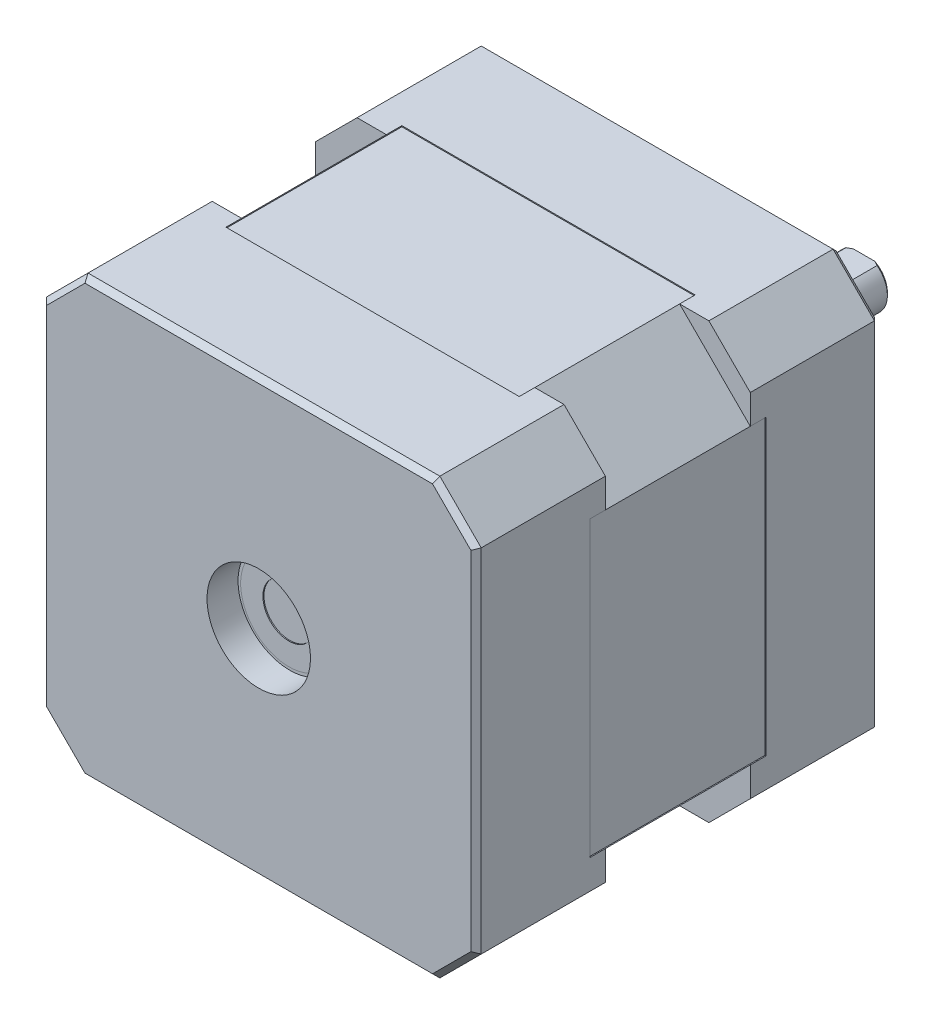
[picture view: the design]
ISO-10303-21;
HEADER;
FILE_DESCRIPTION(('STEP AP214'),'2;1');
FILE_NAME('part.step','',(''),(''),'','','');
FILE_SCHEMA(('AUTOMOTIVE_DESIGN { 1 0 10303 214 1 1 1 1 }'));
ENDSEC;
DATA;
#1=APPLICATION_CONTEXT('core data for automotive mechanical design processes');
#2=APPLICATION_PROTOCOL_DEFINITION('international standard','automotive_design',2000,#1);
#3=PRODUCT_CONTEXT('',#1,'mechanical');
#4=PRODUCT('Part','Part','',(#3));
#5=PRODUCT_RELATED_PRODUCT_CATEGORY('part','',(#4));
#6=PRODUCT_DEFINITION_FORMATION('','',#4);
#7=PRODUCT_DEFINITION_CONTEXT('part definition',#1,'design');
#8=PRODUCT_DEFINITION('design','',#6,#7);
#9=PRODUCT_DEFINITION_SHAPE('','',#8);
#10=(LENGTH_UNIT() NAMED_UNIT(*) SI_UNIT(.MILLI.,.METRE.));
#11=(NAMED_UNIT(*) PLANE_ANGLE_UNIT() SI_UNIT($,.RADIAN.));
#12=(NAMED_UNIT(*) SI_UNIT($,.STERADIAN.) SOLID_ANGLE_UNIT());
#13=UNCERTAINTY_MEASURE_WITH_UNIT(LENGTH_MEASURE(1.E-05),#10,'distance_accuracy_value','');
#14=(GEOMETRIC_REPRESENTATION_CONTEXT(3) GLOBAL_UNCERTAINTY_ASSIGNED_CONTEXT((#13)) GLOBAL_UNIT_ASSIGNED_CONTEXT((#10,
#11,#12)) REPRESENTATION_CONTEXT('',''));
#15=CARTESIAN_POINT('',(0.,0.,0.));
#16=DIRECTION('',(0.,0.,1.));
#17=DIRECTION('',(1.,0.,0.));
#18=AXIS2_PLACEMENT_3D('',#15,#16,#17);
#19=CARTESIAN_POINT('',(0.,0.,36.));
#20=DIRECTION('',(0.,0.,1.));
#21=DIRECTION('',(1.,0.,0.));
#22=AXIS2_PLACEMENT_3D('',#19,#20,#21);
#23=PLANE('',#22);
#24=CARTESIAN_POINT('',(0.,0.,36.));
#25=DIRECTION('',(0.,0.,1.));
#26=DIRECTION('',(1.,0.,0.));
#27=AXIS2_PLACEMENT_3D('',#24,#25,#26);
#28=CIRCLE('',#27,5.);
#29=CARTESIAN_POINT('',(5.,0.,36.));
#30=VERTEX_POINT('',#29);
#31=EDGE_CURVE('E1002',#30,#30,#28,.T.);
#32=ORIENTED_EDGE('',*,*,#31,.T.);
#33=EDGE_LOOP('',(#32));
#34=FACE_BOUND('',#33,.T.);
#35=CARTESIAN_POINT('',(0.,0.,36.));
#36=DIRECTION('',(0.,0.,1.));
#37=DIRECTION('',(1.,0.,0.));
#38=AXIS2_PLACEMENT_3D('',#35,#36,#37);
#39=CIRCLE('',#38,4.65);
#40=CARTESIAN_POINT('',(4.65,0.,36.));
#41=VERTEX_POINT('',#40);
#42=EDGE_CURVE('E995',#41,#41,#39,.T.);
#43=ORIENTED_EDGE('',*,*,#42,.F.);
#44=EDGE_LOOP('',(#43));
#45=FACE_BOUND('',#44,.T.);
#46=ADVANCED_FACE('F35',(#34,#45),#23,.T.);
#47=CARTESIAN_POINT('',(21.,21.,39.));
#48=DIRECTION('',(-1.,0.,0.));
#49=DIRECTION('',(0.,-1.,0.));
#50=AXIS2_PLACEMENT_3D('',#47,#48,#49);
#51=PLANE('',#50);
#52=DIRECTION('',(0.,1.,0.));
#53=VECTOR('',#52,1.);
#54=CARTESIAN_POINT('',(21.,21.,26.5));
#55=LINE('',#54,#53);
#56=CARTESIAN_POINT('',(21.,-17.,26.5));
#57=VERTEX_POINT('',#56);
#58=CARTESIAN_POINT('',(21.0000000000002,-14.1715728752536,26.5));
#59=VERTEX_POINT('',#58);
#60=EDGE_CURVE('E552',#57,#59,#55,.T.);
#61=ORIENTED_EDGE('',*,*,#60,.T.);
#62=DIRECTION('',(0.,0.,-1.));
#63=VECTOR('',#62,1.);
#64=CARTESIAN_POINT('',(21.0000000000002,-14.1715728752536,12.5));
#65=LINE('',#64,#63);
#66=CARTESIAN_POINT('',(21.0000000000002,-14.1715728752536,28.));
#67=VERTEX_POINT('',#66);
#68=EDGE_CURVE('E395',#67,#59,#65,.T.);
#69=ORIENTED_EDGE('',*,*,#68,.F.);
#70=DIRECTION('',(0.,-1.,0.));
#71=VECTOR('',#70,1.);
#72=CARTESIAN_POINT('',(20.9999999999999,14.1715728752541,28.));
#73=LINE('',#72,#71);
#74=CARTESIAN_POINT('',(20.9999999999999,14.1715728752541,28.));
#75=VERTEX_POINT('',#74);
#76=EDGE_CURVE('E392',#75,#67,#73,.T.);
#77=ORIENTED_EDGE('',*,*,#76,.F.);
#78=DIRECTION('',(0.,0.,1.));
#79=VECTOR('',#78,1.);
#80=CARTESIAN_POINT('',(20.9999999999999,14.1715728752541,26.5));
#81=LINE('',#80,#79);
#82=CARTESIAN_POINT('',(20.9999999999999,14.1715728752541,26.5));
#83=VERTEX_POINT('',#82);
#84=EDGE_CURVE('E376',#83,#75,#81,.T.);
#85=ORIENTED_EDGE('',*,*,#84,.F.);
#86=DIRECTION('',(0.,1.,0.));
#87=VECTOR('',#86,1.);
#88=CARTESIAN_POINT('',(21.,21.,26.5));
#89=LINE('',#88,#87);
#90=CARTESIAN_POINT('',(21.,17.,26.5));
#91=VERTEX_POINT('',#90);
#92=EDGE_CURVE('E532',#83,#91,#89,.T.);
#93=ORIENTED_EDGE('',*,*,#92,.T.);
#94=DIRECTION('',(0.,0.,1.));
#95=VECTOR('',#94,1.);
#96=CARTESIAN_POINT('',(21.,17.,39.));
#97=LINE('',#96,#95);
#98=CARTESIAN_POINT('',(21.,17.,38.5));
#99=VERTEX_POINT('',#98);
#100=EDGE_CURVE('E629',#91,#99,#97,.T.);
#101=ORIENTED_EDGE('',*,*,#100,.T.);
#102=DIRECTION('',(0.,-1.,0.));
#103=VECTOR('',#102,1.);
#104=CARTESIAN_POINT('',(21.,-17.,38.5));
#105=LINE('',#104,#103);
#106=CARTESIAN_POINT('',(21.,-17.,38.5));
#107=VERTEX_POINT('',#106);
#108=EDGE_CURVE('E710',#99,#107,#105,.T.);
#109=ORIENTED_EDGE('',*,*,#108,.T.);
#110=DIRECTION('',(0.,0.,-1.));
#111=VECTOR('',#110,1.);
#112=CARTESIAN_POINT('',(21.,-17.,39.));
#113=LINE('',#112,#111);
#114=EDGE_CURVE('E630',#107,#57,#113,.T.);
#115=ORIENTED_EDGE('',*,*,#114,.T.);
#116=EDGE_LOOP('',(#61,#69,#77,#85,#93,#101,#109,#115));
#117=FACE_BOUND('',#116,.T.);
#118=ADVANCED_FACE('F864',(#117),#51,.F.);
#119=CARTESIAN_POINT('',(-21.,-21.,39.));
#120=DIRECTION('',(0.,1.,0.));
#121=DIRECTION('',(0.,0.,1.));
#122=AXIS2_PLACEMENT_3D('',#119,#120,#121);
#123=PLANE('',#122);
#124=DIRECTION('',(1.,0.,0.));
#125=VECTOR('',#124,1.);
#126=CARTESIAN_POINT('',(-21.,-21.,26.5));
#127=LINE('',#126,#125);
#128=CARTESIAN_POINT('',(-17.,-21.,26.5));
#129=VERTEX_POINT('',#128);
#130=CARTESIAN_POINT('',(-14.1715728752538,-21.,26.5));
#131=VERTEX_POINT('',#130);
#132=EDGE_CURVE('E569',#129,#131,#127,.T.);
#133=ORIENTED_EDGE('',*,*,#132,.T.);
#134=DIRECTION('',(0.,0.,-1.));
#135=VECTOR('',#134,1.);
#136=CARTESIAN_POINT('',(-14.1715728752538,-21.,12.5));
#137=LINE('',#136,#135);
#138=CARTESIAN_POINT('',(-14.1715728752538,-21.,28.));
#139=VERTEX_POINT('',#138);
#140=EDGE_CURVE('E424',#139,#131,#137,.T.);
#141=ORIENTED_EDGE('',*,*,#140,.F.);
#142=DIRECTION('',(-1.,0.,0.));
#143=VECTOR('',#142,1.);
#144=CARTESIAN_POINT('',(14.1715728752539,-21.,28.));
#145=LINE('',#144,#143);
#146=CARTESIAN_POINT('',(14.1715728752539,-21.,28.));
#147=VERTEX_POINT('',#146);
#148=EDGE_CURVE('E420',#147,#139,#145,.T.);
#149=ORIENTED_EDGE('',*,*,#148,.F.);
#150=DIRECTION('',(0.,0.,1.));
#151=VECTOR('',#150,1.);
#152=CARTESIAN_POINT('',(14.1715728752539,-21.,26.5));
#153=LINE('',#152,#151);
#154=CARTESIAN_POINT('',(14.1715728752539,-21.,26.5));
#155=VERTEX_POINT('',#154);
#156=EDGE_CURVE('E401',#155,#147,#153,.T.);
#157=ORIENTED_EDGE('',*,*,#156,.F.);
#158=DIRECTION('',(1.,0.,0.));
#159=VECTOR('',#158,1.);
#160=CARTESIAN_POINT('',(-21.,-21.,26.5));
#161=LINE('',#160,#159);
#162=CARTESIAN_POINT('',(17.,-21.,26.5));
#163=VERTEX_POINT('',#162);
#164=EDGE_CURVE('E549',#155,#163,#161,.T.);
#165=ORIENTED_EDGE('',*,*,#164,.T.);
#166=DIRECTION('',(0.,0.,1.));
#167=VECTOR('',#166,1.);
#168=CARTESIAN_POINT('',(17.,-21.,39.));
#169=LINE('',#168,#167);
#170=CARTESIAN_POINT('',(17.,-21.,38.5));
#171=VERTEX_POINT('',#170);
#172=EDGE_CURVE('E637',#163,#171,#169,.T.);
#173=ORIENTED_EDGE('',*,*,#172,.T.);
#174=DIRECTION('',(-1.,0.,0.));
#175=VECTOR('',#174,1.);
#176=CARTESIAN_POINT('',(-17.,-21.,38.5));
#177=LINE('',#176,#175);
#178=CARTESIAN_POINT('',(-17.,-21.,38.5));
#179=VERTEX_POINT('',#178);
#180=EDGE_CURVE('E700',#171,#179,#177,.T.);
#181=ORIENTED_EDGE('',*,*,#180,.T.);
#182=DIRECTION('',(0.,0.,-1.));
#183=VECTOR('',#182,1.);
#184=CARTESIAN_POINT('',(-17.,-21.,39.));
#185=LINE('',#184,#183);
#186=EDGE_CURVE('E634',#179,#129,#185,.T.);
#187=ORIENTED_EDGE('',*,*,#186,.T.);
#188=EDGE_LOOP('',(#133,#141,#149,#157,#165,#173,#181,#187));
#189=FACE_BOUND('',#188,.T.);
#190=ADVANCED_FACE('F850',(#189),#123,.F.);
#191=CARTESIAN_POINT('',(-21.,21.,39.));
#192=DIRECTION('',(1.,0.,0.));
#193=DIRECTION('',(0.,1.,0.));
#194=AXIS2_PLACEMENT_3D('',#191,#192,#193);
#195=PLANE('',#194);
#196=DIRECTION('',(0.,-1.,0.));
#197=VECTOR('',#196,1.);
#198=CARTESIAN_POINT('',(-21.,21.,26.5));
#199=LINE('',#198,#197);
#200=CARTESIAN_POINT('',(-21.,17.,26.5));
#201=VERTEX_POINT('',#200);
#202=CARTESIAN_POINT('',(-21.,14.1715728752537,26.5));
#203=VERTEX_POINT('',#202);
#204=EDGE_CURVE('E511',#201,#203,#199,.T.);
#205=ORIENTED_EDGE('',*,*,#204,.T.);
#206=DIRECTION('',(0.,0.,-1.));
#207=VECTOR('',#206,1.);
#208=CARTESIAN_POINT('',(-21.0000000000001,14.1715728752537,12.5));
#209=LINE('',#208,#207);
#210=CARTESIAN_POINT('',(-21.0000000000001,14.1715728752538,28.));
#211=VERTEX_POINT('',#210);
#212=EDGE_CURVE('E456',#211,#203,#209,.T.);
#213=ORIENTED_EDGE('',*,*,#212,.F.);
#214=DIRECTION('',(0.,1.,0.));
#215=VECTOR('',#214,1.);
#216=CARTESIAN_POINT('',(-21.,-14.1715728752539,28.));
#217=LINE('',#216,#215);
#218=CARTESIAN_POINT('',(-21.,-14.1715728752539,28.));
#219=VERTEX_POINT('',#218);
#220=EDGE_CURVE('E452',#219,#211,#217,.T.);
#221=ORIENTED_EDGE('',*,*,#220,.F.);
#222=DIRECTION('',(0.,0.,1.));
#223=VECTOR('',#222,1.);
#224=CARTESIAN_POINT('',(-21.,-14.1715728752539,26.5));
#225=LINE('',#224,#223);
#226=CARTESIAN_POINT('',(-21.,-14.1715728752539,26.5));
#227=VERTEX_POINT('',#226);
#228=EDGE_CURVE('E430',#227,#219,#225,.T.);
#229=ORIENTED_EDGE('',*,*,#228,.F.);
#230=DIRECTION('',(0.,-1.,0.));
#231=VECTOR('',#230,1.);
#232=CARTESIAN_POINT('',(-21.,21.,26.5));
#233=LINE('',#232,#231);
#234=CARTESIAN_POINT('',(-21.,-17.,26.5));
#235=VERTEX_POINT('',#234);
#236=EDGE_CURVE('E572',#227,#235,#233,.T.);
#237=ORIENTED_EDGE('',*,*,#236,.T.);
#238=DIRECTION('',(0.,0.,1.));
#239=VECTOR('',#238,1.);
#240=CARTESIAN_POINT('',(-21.,-17.,39.));
#241=LINE('',#240,#239);
#242=CARTESIAN_POINT('',(-21.,-17.,38.5));
#243=VERTEX_POINT('',#242);
#244=EDGE_CURVE('E649',#235,#243,#241,.T.);
#245=ORIENTED_EDGE('',*,*,#244,.T.);
#246=DIRECTION('',(0.,1.,0.));
#247=VECTOR('',#246,1.);
#248=CARTESIAN_POINT('',(-21.,17.,38.5));
#249=LINE('',#248,#247);
#250=CARTESIAN_POINT('',(-21.,17.,38.5));
#251=VERTEX_POINT('',#250);
#252=EDGE_CURVE('E690',#243,#251,#249,.T.);
#253=ORIENTED_EDGE('',*,*,#252,.T.);
#254=DIRECTION('',(0.,0.,-1.));
#255=VECTOR('',#254,1.);
#256=CARTESIAN_POINT('',(-21.,17.,39.));
#257=LINE('',#256,#255);
#258=EDGE_CURVE('E654',#251,#201,#257,.T.);
#259=ORIENTED_EDGE('',*,*,#258,.T.);
#260=EDGE_LOOP('',(#205,#213,#221,#229,#237,#245,#253,#259));
#261=FACE_BOUND('',#260,.T.);
#262=ADVANCED_FACE('F855',(#261),#195,.F.);
#263=CARTESIAN_POINT('',(-21.,21.,39.));
#264=DIRECTION('',(0.,-1.,0.));
#265=DIRECTION('',(0.,0.,-1.));
#266=AXIS2_PLACEMENT_3D('',#263,#264,#265);
#267=PLANE('',#266);
#268=DIRECTION('',(-1.,0.,0.));
#269=VECTOR('',#268,1.);
#270=CARTESIAN_POINT('',(-21.,21.,26.5));
#271=LINE('',#270,#269);
#272=CARTESIAN_POINT('',(17.,21.,26.5));
#273=VERTEX_POINT('',#272);
#274=CARTESIAN_POINT('',(14.1715728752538,21.,26.5));
#275=VERTEX_POINT('',#274);
#276=EDGE_CURVE('E529',#273,#275,#271,.T.);
#277=ORIENTED_EDGE('',*,*,#276,.T.);
#278=DIRECTION('',(0.,0.,-1.));
#279=VECTOR('',#278,1.);
#280=CARTESIAN_POINT('',(14.1715728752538,21.,12.5));
#281=LINE('',#280,#279);
#282=CARTESIAN_POINT('',(14.1715728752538,21.,28.));
#283=VERTEX_POINT('',#282);
#284=EDGE_CURVE('E488',#283,#275,#281,.T.);
#285=ORIENTED_EDGE('',*,*,#284,.F.);
#286=DIRECTION('',(1.,0.,0.));
#287=VECTOR('',#286,1.);
#288=CARTESIAN_POINT('',(-14.1715728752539,21.,28.));
#289=LINE('',#288,#287);
#290=CARTESIAN_POINT('',(-14.1715728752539,21.,28.));
#291=VERTEX_POINT('',#290);
#292=EDGE_CURVE('E484',#291,#283,#289,.T.);
#293=ORIENTED_EDGE('',*,*,#292,.F.);
#294=DIRECTION('',(0.,0.,1.));
#295=VECTOR('',#294,1.);
#296=CARTESIAN_POINT('',(-14.1715728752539,21.,26.5));
#297=LINE('',#296,#295);
#298=CARTESIAN_POINT('',(-14.1715728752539,21.,26.5));
#299=VERTEX_POINT('',#298);
#300=EDGE_CURVE('E462',#299,#291,#297,.T.);
#301=ORIENTED_EDGE('',*,*,#300,.F.);
#302=DIRECTION('',(-1.,0.,0.));
#303=VECTOR('',#302,1.);
#304=CARTESIAN_POINT('',(-21.,21.,26.5));
#305=LINE('',#304,#303);
#306=CARTESIAN_POINT('',(-17.,21.,26.5));
#307=VERTEX_POINT('',#306);
#308=EDGE_CURVE('E514',#299,#307,#305,.T.);
#309=ORIENTED_EDGE('',*,*,#308,.T.);
#310=DIRECTION('',(0.,0.,1.));
#311=VECTOR('',#310,1.);
#312=CARTESIAN_POINT('',(-17.,21.,39.));
#313=LINE('',#312,#311);
#314=CARTESIAN_POINT('',(-17.,21.,38.5));
#315=VERTEX_POINT('',#314);
#316=EDGE_CURVE('E641',#307,#315,#313,.T.);
#317=ORIENTED_EDGE('',*,*,#316,.T.);
#318=DIRECTION('',(1.,0.,0.));
#319=VECTOR('',#318,1.);
#320=CARTESIAN_POINT('',(17.,21.,38.5));
#321=LINE('',#320,#319);
#322=CARTESIAN_POINT('',(17.,21.,38.5));
#323=VERTEX_POINT('',#322);
#324=EDGE_CURVE('E680',#315,#323,#321,.T.);
#325=ORIENTED_EDGE('',*,*,#324,.T.);
#326=DIRECTION('',(0.,0.,-1.));
#327=VECTOR('',#326,1.);
#328=CARTESIAN_POINT('',(17.,21.,39.));
#329=LINE('',#328,#327);
#330=EDGE_CURVE('E646',#323,#273,#329,.T.);
#331=ORIENTED_EDGE('',*,*,#330,.T.);
#332=EDGE_LOOP('',(#277,#285,#293,#301,#309,#317,#325,#331));
#333=FACE_BOUND('',#332,.T.);
#334=ADVANCED_FACE('F860',(#333),#267,.F.);
#335=CARTESIAN_POINT('',(-21.,17.,39.));
#336=DIRECTION('',(0.707106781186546,-0.707106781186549,0.));
#337=DIRECTION('',(0.,0.,-1.));
#338=AXIS2_PLACEMENT_3D('',#335,#336,#337);
#339=PLANE('',#338);
#340=DIRECTION('',(-0.707106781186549,-0.707106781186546,0.));
#341=VECTOR('',#340,1.);
#342=CARTESIAN_POINT('',(-21.,17.,26.5));
#343=LINE('',#342,#341);
#344=EDGE_CURVE('E1035',#201,#307,#343,.F.);
#345=ORIENTED_EDGE('',*,*,#344,.F.);
#346=ORIENTED_EDGE('',*,*,#258,.F.);
#347=DIRECTION('',(-0.707106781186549,-0.707106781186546,0.));
#348=VECTOR('',#347,1.);
#349=CARTESIAN_POINT('',(-21.,17.,38.5));
#350=LINE('',#349,#348);
#351=EDGE_CURVE('E684',#251,#315,#350,.F.);
#352=ORIENTED_EDGE('',*,*,#351,.T.);
#353=ORIENTED_EDGE('',*,*,#316,.F.);
#354=EDGE_LOOP('',(#345,#346,#352,#353));
#355=FACE_BOUND('',#354,.T.);
#356=ADVANCED_FACE('F879',(#355),#339,.F.);
#357=CARTESIAN_POINT('',(17.,21.,39.));
#358=DIRECTION('',(-0.707106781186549,-0.707106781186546,0.));
#359=DIRECTION('',(0.,0.,-1.));
#360=AXIS2_PLACEMENT_3D('',#357,#358,#359);
#361=PLANE('',#360);
#362=DIRECTION('',(-0.707106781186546,0.707106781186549,0.));
#363=VECTOR('',#362,1.);
#364=CARTESIAN_POINT('',(17.,21.,26.5));
#365=LINE('',#364,#363);
#366=EDGE_CURVE('E1060',#273,#91,#365,.F.);
#367=ORIENTED_EDGE('',*,*,#366,.F.);
#368=ORIENTED_EDGE('',*,*,#330,.F.);
#369=DIRECTION('',(-0.707106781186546,0.707106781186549,0.));
#370=VECTOR('',#369,1.);
#371=CARTESIAN_POINT('',(17.,21.,38.5));
#372=LINE('',#371,#370);
#373=EDGE_CURVE('E674',#323,#99,#372,.F.);
#374=ORIENTED_EDGE('',*,*,#373,.T.);
#375=ORIENTED_EDGE('',*,*,#100,.F.);
#376=EDGE_LOOP('',(#367,#368,#374,#375));
#377=FACE_BOUND('',#376,.T.);
#378=ADVANCED_FACE('F874',(#377),#361,.F.);
#379=CARTESIAN_POINT('',(21.,-17.,39.));
#380=DIRECTION('',(-0.707106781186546,0.707106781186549,0.));
#381=DIRECTION('',(0.,0.,-1.));
#382=AXIS2_PLACEMENT_3D('',#379,#380,#381);
#383=PLANE('',#382);
#384=DIRECTION('',(0.707106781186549,0.707106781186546,0.));
#385=VECTOR('',#384,1.);
#386=CARTESIAN_POINT('',(21.,-17.,26.5));
#387=LINE('',#386,#385);
#388=EDGE_CURVE('E1053',#57,#163,#387,.F.);
#389=ORIENTED_EDGE('',*,*,#388,.F.);
#390=ORIENTED_EDGE('',*,*,#114,.F.);
#391=DIRECTION('',(0.707106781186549,0.707106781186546,0.));
#392=VECTOR('',#391,1.);
#393=CARTESIAN_POINT('',(21.,-17.,38.5));
#394=LINE('',#393,#392);
#395=EDGE_CURVE('E704',#107,#171,#394,.F.);
#396=ORIENTED_EDGE('',*,*,#395,.T.);
#397=ORIENTED_EDGE('',*,*,#172,.F.);
#398=EDGE_LOOP('',(#389,#390,#396,#397));
#399=FACE_BOUND('',#398,.T.);
#400=ADVANCED_FACE('F869',(#399),#383,.F.);
#401=CARTESIAN_POINT('',(-17.,-21.,39.));
#402=DIRECTION('',(0.707106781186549,0.707106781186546,0.));
#403=DIRECTION('',(0.,0.,-1.));
#404=AXIS2_PLACEMENT_3D('',#401,#402,#403);
#405=PLANE('',#404);
#406=DIRECTION('',(0.707106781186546,-0.707106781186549,0.));
#407=VECTOR('',#406,1.);
#408=CARTESIAN_POINT('',(-17.,-21.,26.5));
#409=LINE('',#408,#407);
#410=EDGE_CURVE('E1044',#129,#235,#409,.F.);
#411=ORIENTED_EDGE('',*,*,#410,.F.);
#412=ORIENTED_EDGE('',*,*,#186,.F.);
#413=DIRECTION('',(0.707106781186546,-0.707106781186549,0.));
#414=VECTOR('',#413,1.);
#415=CARTESIAN_POINT('',(-17.,-21.,38.5));
#416=LINE('',#415,#414);
#417=EDGE_CURVE('E694',#179,#243,#416,.F.);
#418=ORIENTED_EDGE('',*,*,#417,.T.);
#419=ORIENTED_EDGE('',*,*,#244,.F.);
#420=EDGE_LOOP('',(#411,#412,#418,#419));
#421=FACE_BOUND('',#420,.T.);
#422=ADVANCED_FACE('F834',(#421),#405,.F.);
#423=CARTESIAN_POINT('',(0.,0.,0.5));
#424=DIRECTION('',(0.,0.,-1.));
#425=DIRECTION('',(-1.,0.,0.));
#426=AXIS2_PLACEMENT_3D('',#423,#424,#425);
#427=PLANE('',#426);
#428=CARTESIAN_POINT('',(0.,0.,0.5));
#429=DIRECTION('',(0.,0.,-1.));
#430=DIRECTION('',(-1.,0.,0.));
#431=AXIS2_PLACEMENT_3D('',#428,#429,#430);
#432=CIRCLE('',#431,4.75);
#433=CARTESIAN_POINT('',(-4.75,0.,0.5));
#434=VERTEX_POINT('',#433);
#435=EDGE_CURVE('E782',#434,#434,#432,.F.);
#436=ORIENTED_EDGE('',*,*,#435,.F.);
#437=EDGE_LOOP('',(#436));
#438=FACE_BOUND('',#437,.T.);
#439=CARTESIAN_POINT('',(0.,0.,0.5));
#440=DIRECTION('',(0.,0.,-1.));
#441=DIRECTION('',(-1.,0.,0.));
#442=AXIS2_PLACEMENT_3D('',#439,#440,#441);
#443=CIRCLE('',#442,2.5);
#444=CARTESIAN_POINT('',(-2.5,0.,0.5));
#445=VERTEX_POINT('',#444);
#446=EDGE_CURVE('E612',#445,#445,#443,.T.);
#447=ORIENTED_EDGE('',*,*,#446,.F.);
#448=EDGE_LOOP('',(#447));
#449=FACE_BOUND('',#448,.T.);
#450=ADVANCED_FACE('F830',(#438,#449),#427,.T.);
#451=CARTESIAN_POINT('',(0.,0.,0.5));
#452=DIRECTION('',(0.,0.,-1.));
#453=DIRECTION('',(-1.,0.,0.));
#454=AXIS2_PLACEMENT_3D('',#451,#452,#453);
#455=CIRCLE('',#454,14.);
#456=CARTESIAN_POINT('',(-14.,0.,0.5));
#457=VERTEX_POINT('',#456);
#458=EDGE_CURVE('E731',#457,#457,#455,.T.);
#459=ORIENTED_EDGE('',*,*,#458,.T.);
#460=EDGE_LOOP('',(#459));
#461=FACE_BOUND('',#460,.T.);
#462=CARTESIAN_POINT('',(0.,0.,0.5));
#463=DIRECTION('',(0.,0.,-1.));
#464=DIRECTION('',(-1.,0.,0.));
#465=AXIS2_PLACEMENT_3D('',#462,#463,#464);
#466=CIRCLE('',#465,11.);
#467=CARTESIAN_POINT('',(-11.,0.,0.5));
#468=VERTEX_POINT('',#467);
#469=EDGE_CURVE('E618',#468,#468,#466,.T.);
#470=ORIENTED_EDGE('',*,*,#469,.F.);
#471=EDGE_LOOP('',(#470));
#472=FACE_BOUND('',#471,.T.);
#473=ADVANCED_FACE('F833',(#461,#472),#427,.T.);
#474=DIRECTION('',(0.,1.,0.));
#475=VECTOR('',#474,1.);
#476=CARTESIAN_POINT('',(20.9999999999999,14.1715728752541,11.));
#477=LINE('',#476,#475);
#478=CARTESIAN_POINT('',(21.0000000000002,-14.1715728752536,11.));
#479=VERTEX_POINT('',#478);
#480=CARTESIAN_POINT('',(20.9999999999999,14.1715728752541,11.));
#481=VERTEX_POINT('',#480);
#482=EDGE_CURVE('E370',#479,#481,#477,.T.);
#483=ORIENTED_EDGE('',*,*,#482,.F.);
#484=CARTESIAN_POINT('',(21.0000000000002,-14.1715728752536,12.5));
#485=VERTEX_POINT('',#484);
#486=EDGE_CURVE('E394',#485,#479,#65,.T.);
#487=ORIENTED_EDGE('',*,*,#486,.F.);
#488=DIRECTION('',(0.,-1.,0.));
#489=VECTOR('',#488,1.);
#490=CARTESIAN_POINT('',(21.,21.,12.5));
#491=LINE('',#490,#489);
#492=CARTESIAN_POINT('',(21.,-17.,12.5));
#493=VERTEX_POINT('',#492);
#494=EDGE_CURVE('E546',#485,#493,#491,.T.);
#495=ORIENTED_EDGE('',*,*,#494,.T.);
#496=CARTESIAN_POINT('',(21.,-17.,0.5));
#497=VERTEX_POINT('',#496);
#498=EDGE_CURVE('E628',#493,#497,#113,.T.);
#499=ORIENTED_EDGE('',*,*,#498,.T.);
#500=DIRECTION('',(0.,1.,0.));
#501=VECTOR('',#500,1.);
#502=CARTESIAN_POINT('',(21.,21.,0.5));
#503=LINE('',#502,#501);
#504=CARTESIAN_POINT('',(21.,17.,0.5));
#505=VERTEX_POINT('',#504);
#506=EDGE_CURVE('E712',#497,#505,#503,.T.);
#507=ORIENTED_EDGE('',*,*,#506,.T.);
#508=CARTESIAN_POINT('',(21.,17.,12.5));
#509=VERTEX_POINT('',#508);
#510=EDGE_CURVE('E625',#505,#509,#97,.T.);
#511=ORIENTED_EDGE('',*,*,#510,.T.);
#512=DIRECTION('',(0.,-1.,0.));
#513=VECTOR('',#512,1.);
#514=CARTESIAN_POINT('',(21.,21.,12.5));
#515=LINE('',#514,#513);
#516=CARTESIAN_POINT('',(21.,14.1715728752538,12.5));
#517=VERTEX_POINT('',#516);
#518=EDGE_CURVE('E59',#509,#517,#515,.T.);
#519=ORIENTED_EDGE('',*,*,#518,.T.);
#520=EDGE_CURVE('E390',#481,#517,#81,.T.);
#521=ORIENTED_EDGE('',*,*,#520,.F.);
#522=EDGE_LOOP('',(#483,#487,#495,#499,#507,#511,#519,#521));
#523=FACE_BOUND('',#522,.T.);
#524=ADVANCED_FACE('F858',(#523),#51,.F.);
#525=DIRECTION('',(-1.,0.,0.));
#526=VECTOR('',#525,1.);
#527=CARTESIAN_POINT('',(-14.1715728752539,21.,11.));
#528=LINE('',#527,#526);
#529=CARTESIAN_POINT('',(14.1715728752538,21.,11.));
#530=VERTEX_POINT('',#529);
#531=CARTESIAN_POINT('',(-14.1715728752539,21.,11.));
#532=VERTEX_POINT('',#531);
#533=EDGE_CURVE('E473',#530,#532,#528,.T.);
#534=ORIENTED_EDGE('',*,*,#533,.F.);
#535=CARTESIAN_POINT('',(14.1715728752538,21.,12.5));
#536=VERTEX_POINT('',#535);
#537=EDGE_CURVE('E487',#536,#530,#281,.T.);
#538=ORIENTED_EDGE('',*,*,#537,.F.);
#539=DIRECTION('',(1.,0.,0.));
#540=VECTOR('',#539,1.);
#541=CARTESIAN_POINT('',(-21.,21.,12.5));
#542=LINE('',#541,#540);
#543=CARTESIAN_POINT('',(17.,21.,12.5));
#544=VERTEX_POINT('',#543);
#545=EDGE_CURVE('E525',#536,#544,#542,.T.);
#546=ORIENTED_EDGE('',*,*,#545,.T.);
#547=CARTESIAN_POINT('',(17.,21.,0.5));
#548=VERTEX_POINT('',#547);
#549=EDGE_CURVE('E645',#544,#548,#329,.T.);
#550=ORIENTED_EDGE('',*,*,#549,.T.);
#551=DIRECTION('',(-1.,0.,0.));
#552=VECTOR('',#551,1.);
#553=CARTESIAN_POINT('',(-21.,21.,0.5));
#554=LINE('',#553,#552);
#555=CARTESIAN_POINT('',(-17.,21.,0.5));
#556=VERTEX_POINT('',#555);
#557=EDGE_CURVE('E682',#548,#556,#554,.T.);
#558=ORIENTED_EDGE('',*,*,#557,.T.);
#559=CARTESIAN_POINT('',(-17.,21.,12.5));
#560=VERTEX_POINT('',#559);
#561=EDGE_CURVE('E642',#556,#560,#313,.T.);
#562=ORIENTED_EDGE('',*,*,#561,.T.);
#563=DIRECTION('',(1.,0.,0.));
#564=VECTOR('',#563,1.);
#565=CARTESIAN_POINT('',(-21.,21.,12.5));
#566=LINE('',#565,#564);
#567=CARTESIAN_POINT('',(-14.1715728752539,21.,12.5));
#568=VERTEX_POINT('',#567);
#569=EDGE_CURVE('E51',#560,#568,#566,.T.);
#570=ORIENTED_EDGE('',*,*,#569,.T.);
#571=EDGE_CURVE('E482',#532,#568,#297,.T.);
#572=ORIENTED_EDGE('',*,*,#571,.F.);
#573=EDGE_LOOP('',(#534,#538,#546,#550,#558,#562,#570,#572));
#574=FACE_BOUND('',#573,.T.);
#575=ADVANCED_FACE('F853',(#574),#267,.F.);
#576=DIRECTION('',(0.,-1.,0.));
#577=VECTOR('',#576,1.);
#578=CARTESIAN_POINT('',(-21.,-14.1715728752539,11.));
#579=LINE('',#578,#577);
#580=CARTESIAN_POINT('',(-21.0000000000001,14.1715728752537,11.));
#581=VERTEX_POINT('',#580);
#582=CARTESIAN_POINT('',(-21.,-14.1715728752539,11.));
#583=VERTEX_POINT('',#582);
#584=EDGE_CURVE('E441',#581,#583,#579,.T.);
#585=ORIENTED_EDGE('',*,*,#584,.F.);
#586=CARTESIAN_POINT('',(-21.0000000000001,14.1715728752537,12.5));
#587=VERTEX_POINT('',#586);
#588=EDGE_CURVE('E455',#587,#581,#209,.T.);
#589=ORIENTED_EDGE('',*,*,#588,.F.);
#590=DIRECTION('',(0.,1.,0.));
#591=VECTOR('',#590,1.);
#592=CARTESIAN_POINT('',(-21.,21.,12.5));
#593=LINE('',#592,#591);
#594=CARTESIAN_POINT('',(-21.,17.,12.5));
#595=VERTEX_POINT('',#594);
#596=EDGE_CURVE('E507',#587,#595,#593,.T.);
#597=ORIENTED_EDGE('',*,*,#596,.T.);
#598=CARTESIAN_POINT('',(-21.,17.,0.5));
#599=VERTEX_POINT('',#598);
#600=EDGE_CURVE('E653',#595,#599,#257,.T.);
#601=ORIENTED_EDGE('',*,*,#600,.T.);
#602=DIRECTION('',(0.,-1.,0.));
#603=VECTOR('',#602,1.);
#604=CARTESIAN_POINT('',(-21.,21.,0.5));
#605=LINE('',#604,#603);
#606=CARTESIAN_POINT('',(-21.,-17.,0.5));
#607=VERTEX_POINT('',#606);
#608=EDGE_CURVE('E692',#599,#607,#605,.T.);
#609=ORIENTED_EDGE('',*,*,#608,.T.);
#610=CARTESIAN_POINT('',(-21.,-17.,12.5));
#611=VERTEX_POINT('',#610);
#612=EDGE_CURVE('E650',#607,#611,#241,.T.);
#613=ORIENTED_EDGE('',*,*,#612,.T.);
#614=DIRECTION('',(0.,1.,0.));
#615=VECTOR('',#614,1.);
#616=CARTESIAN_POINT('',(-21.,21.,12.5));
#617=LINE('',#616,#615);
#618=CARTESIAN_POINT('',(-21.,-14.1715728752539,12.5));
#619=VERTEX_POINT('',#618);
#620=EDGE_CURVE('E566',#611,#619,#617,.T.);
#621=ORIENTED_EDGE('',*,*,#620,.T.);
#622=EDGE_CURVE('E450',#583,#619,#225,.T.);
#623=ORIENTED_EDGE('',*,*,#622,.F.);
#624=EDGE_LOOP('',(#585,#589,#597,#601,#609,#613,#621,#623));
#625=FACE_BOUND('',#624,.T.);
#626=ADVANCED_FACE('F848',(#625),#195,.F.);
#627=DIRECTION('',(1.,0.,0.));
#628=VECTOR('',#627,1.);
#629=CARTESIAN_POINT('',(14.1715728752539,-21.,11.));
#630=LINE('',#629,#628);
#631=CARTESIAN_POINT('',(-14.1715728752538,-21.,11.));
#632=VERTEX_POINT('',#631);
#633=CARTESIAN_POINT('',(14.1715728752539,-21.,11.));
#634=VERTEX_POINT('',#633);
#635=EDGE_CURVE('E409',#632,#634,#630,.T.);
#636=ORIENTED_EDGE('',*,*,#635,.F.);
#637=CARTESIAN_POINT('',(-14.1715728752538,-21.,12.5));
#638=VERTEX_POINT('',#637);
#639=EDGE_CURVE('E423',#638,#632,#137,.T.);
#640=ORIENTED_EDGE('',*,*,#639,.F.);
#641=DIRECTION('',(-1.,0.,0.));
#642=VECTOR('',#641,1.);
#643=CARTESIAN_POINT('',(-21.,-21.,12.5));
#644=LINE('',#643,#642);
#645=CARTESIAN_POINT('',(-17.,-21.,12.5));
#646=VERTEX_POINT('',#645);
#647=EDGE_CURVE('E563',#638,#646,#644,.T.);
#648=ORIENTED_EDGE('',*,*,#647,.T.);
#649=CARTESIAN_POINT('',(-17.,-21.,0.5));
#650=VERTEX_POINT('',#649);
#651=EDGE_CURVE('E633',#646,#650,#185,.T.);
#652=ORIENTED_EDGE('',*,*,#651,.T.);
#653=DIRECTION('',(1.,0.,0.));
#654=VECTOR('',#653,1.);
#655=CARTESIAN_POINT('',(-21.,-21.,0.5));
#656=LINE('',#655,#654);
#657=CARTESIAN_POINT('',(17.,-21.,0.5));
#658=VERTEX_POINT('',#657);
#659=EDGE_CURVE('E702',#650,#658,#656,.T.);
#660=ORIENTED_EDGE('',*,*,#659,.T.);
#661=CARTESIAN_POINT('',(17.,-21.,12.5));
#662=VERTEX_POINT('',#661);
#663=EDGE_CURVE('E638',#658,#662,#169,.T.);
#664=ORIENTED_EDGE('',*,*,#663,.T.);
#665=DIRECTION('',(-1.,0.,0.));
#666=VECTOR('',#665,1.);
#667=CARTESIAN_POINT('',(-21.,-21.,12.5));
#668=LINE('',#667,#666);
#669=CARTESIAN_POINT('',(14.1715728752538,-21.,12.5));
#670=VERTEX_POINT('',#669);
#671=EDGE_CURVE('E543',#662,#670,#668,.T.);
#672=ORIENTED_EDGE('',*,*,#671,.T.);
#673=EDGE_CURVE('E418',#634,#670,#153,.T.);
#674=ORIENTED_EDGE('',*,*,#673,.F.);
#675=EDGE_LOOP('',(#636,#640,#648,#652,#660,#664,#672,#674));
#676=FACE_BOUND('',#675,.T.);
#677=ADVANCED_FACE('F840',(#676),#123,.F.);
#678=CARTESIAN_POINT('',(0.,0.,39.));
#679=DIRECTION('',(0.,0.,1.));
#680=DIRECTION('',(1.,0.,0.));
#681=AXIS2_PLACEMENT_3D('',#678,#679,#680);
#682=PLANE('',#681);
#683=CARTESIAN_POINT('',(0.,0.,39.));
#684=DIRECTION('',(0.,0.,1.));
#685=DIRECTION('',(1.,0.,0.));
#686=AXIS2_PLACEMENT_3D('',#683,#684,#685);
#687=CIRCLE('',#686,5.);
#688=CARTESIAN_POINT('',(5.,0.,39.));
#689=VERTEX_POINT('',#688);
#690=EDGE_CURVE('E1000',#689,#689,#687,.T.);
#691=ORIENTED_EDGE('',*,*,#690,.F.);
#692=EDGE_LOOP('',(#691));
#693=FACE_BOUND('',#692,.T.);
#694=DIRECTION('',(0.,-1.,0.));
#695=VECTOR('',#694,1.);
#696=CARTESIAN_POINT('',(-20.5,-17.,39.));
#697=LINE('',#696,#695);
#698=CARTESIAN_POINT('',(-20.5,16.7928932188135,39.));
#699=VERTEX_POINT('',#698);
#700=CARTESIAN_POINT('',(-20.5,-16.7928932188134,39.));
#701=VERTEX_POINT('',#700);
#702=EDGE_CURVE('E726',#699,#701,#697,.T.);
#703=ORIENTED_EDGE('',*,*,#702,.T.);
#704=DIRECTION('',(0.707106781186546,-0.707106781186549,0.));
#705=VECTOR('',#704,1.);
#706=CARTESIAN_POINT('',(-18.6464466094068,-18.6464466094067,39.));
#707=LINE('',#706,#705);
#708=CARTESIAN_POINT('',(-16.7928932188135,-20.5,39.));
#709=VERTEX_POINT('',#708);
#710=EDGE_CURVE('E728',#701,#709,#707,.T.);
#711=ORIENTED_EDGE('',*,*,#710,.T.);
#712=DIRECTION('',(1.,0.,0.));
#713=VECTOR('',#712,1.);
#714=CARTESIAN_POINT('',(17.,-20.5,39.));
#715=LINE('',#714,#713);
#716=CARTESIAN_POINT('',(16.7928932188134,-20.5,39.));
#717=VERTEX_POINT('',#716);
#718=EDGE_CURVE('E714',#709,#717,#715,.T.);
#719=ORIENTED_EDGE('',*,*,#718,.T.);
#720=DIRECTION('',(0.707106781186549,0.707106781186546,0.));
#721=VECTOR('',#720,1.);
#722=CARTESIAN_POINT('',(18.6464466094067,-18.6464466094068,39.));
#723=LINE('',#722,#721);
#724=CARTESIAN_POINT('',(20.5,-16.7928932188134,39.));
#725=VERTEX_POINT('',#724);
#726=EDGE_CURVE('E716',#717,#725,#723,.T.);
#727=ORIENTED_EDGE('',*,*,#726,.T.);
#728=DIRECTION('',(0.,1.,0.));
#729=VECTOR('',#728,1.);
#730=CARTESIAN_POINT('',(20.5,17.,39.));
#731=LINE('',#730,#729);
#732=CARTESIAN_POINT('',(20.5,16.7928932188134,39.));
#733=VERTEX_POINT('',#732);
#734=EDGE_CURVE('E718',#725,#733,#731,.T.);
#735=ORIENTED_EDGE('',*,*,#734,.T.);
#736=DIRECTION('',(-0.707106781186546,0.707106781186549,0.));
#737=VECTOR('',#736,1.);
#738=CARTESIAN_POINT('',(18.6464466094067,18.6464466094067,39.));
#739=LINE('',#738,#737);
#740=CARTESIAN_POINT('',(16.7928932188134,20.5,39.));
#741=VERTEX_POINT('',#740);
#742=EDGE_CURVE('E720',#733,#741,#739,.T.);
#743=ORIENTED_EDGE('',*,*,#742,.T.);
#744=DIRECTION('',(-1.,0.,0.));
#745=VECTOR('',#744,1.);
#746=CARTESIAN_POINT('',(-17.,20.5,39.));
#747=LINE('',#746,#745);
#748=CARTESIAN_POINT('',(-16.7928932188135,20.5,39.));
#749=VERTEX_POINT('',#748);
#750=EDGE_CURVE('E722',#741,#749,#747,.T.);
#751=ORIENTED_EDGE('',*,*,#750,.T.);
#752=DIRECTION('',(-0.707106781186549,-0.707106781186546,0.));
#753=VECTOR('',#752,1.);
#754=CARTESIAN_POINT('',(-18.6464466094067,18.6464466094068,39.));
#755=LINE('',#754,#753);
#756=EDGE_CURVE('E724',#749,#699,#755,.T.);
#757=ORIENTED_EDGE('',*,*,#756,.T.);
#758=EDGE_LOOP('',(#703,#711,#719,#727,#735,#743,#751,#757));
#759=FACE_BOUND('',#758,.T.);
#760=ADVANCED_FACE('F836',(#693,#759),#682,.T.);
#761=CARTESIAN_POINT('',(0.,0.,0.));
#762=DIRECTION('',(0.,0.,1.));
#763=DIRECTION('',(1.,0.,0.));
#764=AXIS2_PLACEMENT_3D('',#761,#762,#763);
#765=PLANE('',#764);
#766=CARTESIAN_POINT('',(15.3500000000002,-15.3499999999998,0.));
#767=DIRECTION('',(0.,0.,-1.));
#768=DIRECTION('',(0.,1.,0.));
#769=AXIS2_PLACEMENT_3D('',#766,#767,#768);
#770=CIRCLE('',#769,1.5);
#771=CARTESIAN_POINT('',(15.3500000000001,-13.8499999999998,0.));
#772=VERTEX_POINT('',#771);
#773=EDGE_CURVE('E577',#772,#772,#770,.T.);
#774=ORIENTED_EDGE('',*,*,#773,.F.);
#775=EDGE_LOOP('',(#774));
#776=FACE_BOUND('',#775,.T.);
#777=CARTESIAN_POINT('',(-15.35,-15.35,0.));
#778=DIRECTION('',(0.,0.,-1.));
#779=DIRECTION('',(1.,0.,0.));
#780=AXIS2_PLACEMENT_3D('',#777,#778,#779);
#781=CIRCLE('',#780,1.5);
#782=CARTESIAN_POINT('',(-13.85,-15.35,0.));
#783=VERTEX_POINT('',#782);
#784=EDGE_CURVE('E581',#783,#783,#781,.T.);
#785=ORIENTED_EDGE('',*,*,#784,.F.);
#786=EDGE_LOOP('',(#785));
#787=FACE_BOUND('',#786,.T.);
#788=CARTESIAN_POINT('',(-15.3500000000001,15.3499999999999,0.));
#789=DIRECTION('',(0.,0.,-1.));
#790=DIRECTION('',(0.,-1.,0.));
#791=AXIS2_PLACEMENT_3D('',#788,#789,#790);
#792=CIRCLE('',#791,1.5);
#793=CARTESIAN_POINT('',(-15.3500000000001,13.8499999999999,0.));
#794=VERTEX_POINT('',#793);
#795=EDGE_CURVE('E587',#794,#794,#792,.T.);
#796=ORIENTED_EDGE('',*,*,#795,.F.);
#797=EDGE_LOOP('',(#796));
#798=FACE_BOUND('',#797,.T.);
#799=CARTESIAN_POINT('',(15.35,15.35,0.));
#800=DIRECTION('',(0.,0.,-1.));
#801=DIRECTION('',(-1.,0.,0.));
#802=AXIS2_PLACEMENT_3D('',#799,#800,#801);
#803=CIRCLE('',#802,1.5);
#804=CARTESIAN_POINT('',(13.85,15.35,0.));
#805=VERTEX_POINT('',#804);
#806=EDGE_CURVE('E593',#805,#805,#803,.T.);
#807=ORIENTED_EDGE('',*,*,#806,.F.);
#808=EDGE_LOOP('',(#807));
#809=FACE_BOUND('',#808,.T.);
#810=CARTESIAN_POINT('',(0.,0.,0.));
#811=DIRECTION('',(0.,0.,1.));
#812=DIRECTION('',(1.,0.,0.));
#813=AXIS2_PLACEMENT_3D('',#810,#811,#812);
#814=CIRCLE('',#813,14.5);
#815=CARTESIAN_POINT('',(14.5,0.,0.));
#816=VERTEX_POINT('',#815);
#817=EDGE_CURVE('E779',#816,#816,#814,.T.);
#818=ORIENTED_EDGE('',*,*,#817,.T.);
#819=EDGE_LOOP('',(#818));
#820=FACE_BOUND('',#819,.T.);
#821=DIRECTION('',(1.,0.,0.));
#822=VECTOR('',#821,1.);
#823=CARTESIAN_POINT('',(0.,20.5,0.));
#824=LINE('',#823,#822);
#825=CARTESIAN_POINT('',(-16.7928932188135,20.5,0.));
#826=VERTEX_POINT('',#825);
#827=CARTESIAN_POINT('',(16.7928932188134,20.5,0.));
#828=VERTEX_POINT('',#827);
#829=EDGE_CURVE('E669',#826,#828,#824,.T.);
#830=ORIENTED_EDGE('',*,*,#829,.T.);
#831=DIRECTION('',(0.707106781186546,-0.707106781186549,0.));
#832=VECTOR('',#831,1.);
#833=CARTESIAN_POINT('',(20.6464466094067,16.6464466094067,0.));
#834=LINE('',#833,#832);
#835=CARTESIAN_POINT('',(20.5,16.7928932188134,0.));
#836=VERTEX_POINT('',#835);
#837=EDGE_CURVE('E671',#828,#836,#834,.T.);
#838=ORIENTED_EDGE('',*,*,#837,.T.);
#839=DIRECTION('',(0.,-1.,0.));
#840=VECTOR('',#839,1.);
#841=CARTESIAN_POINT('',(20.5,0.,0.));
#842=LINE('',#841,#840);
#843=CARTESIAN_POINT('',(20.5,-16.7928932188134,0.));
#844=VERTEX_POINT('',#843);
#845=EDGE_CURVE('E657',#836,#844,#842,.T.);
#846=ORIENTED_EDGE('',*,*,#845,.T.);
#847=DIRECTION('',(-0.707106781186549,-0.707106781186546,0.));
#848=VECTOR('',#847,1.);
#849=CARTESIAN_POINT('',(16.6464466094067,-20.6464466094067,0.));
#850=LINE('',#849,#848);
#851=CARTESIAN_POINT('',(16.7928932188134,-20.5,0.));
#852=VERTEX_POINT('',#851);
#853=EDGE_CURVE('E659',#844,#852,#850,.T.);
#854=ORIENTED_EDGE('',*,*,#853,.T.);
#855=DIRECTION('',(-1.,0.,0.));
#856=VECTOR('',#855,1.);
#857=CARTESIAN_POINT('',(0.,-20.5,0.));
#858=LINE('',#857,#856);
#859=CARTESIAN_POINT('',(-16.7928932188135,-20.5,0.));
#860=VERTEX_POINT('',#859);
#861=EDGE_CURVE('E661',#852,#860,#858,.T.);
#862=ORIENTED_EDGE('',*,*,#861,.T.);
#863=DIRECTION('',(-0.707106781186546,0.707106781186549,0.));
#864=VECTOR('',#863,1.);
#865=CARTESIAN_POINT('',(-20.6464466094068,-16.6464466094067,0.));
#866=LINE('',#865,#864);
#867=CARTESIAN_POINT('',(-20.5,-16.7928932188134,0.));
#868=VERTEX_POINT('',#867);
#869=EDGE_CURVE('E663',#860,#868,#866,.T.);
#870=ORIENTED_EDGE('',*,*,#869,.T.);
#871=DIRECTION('',(0.,1.,0.));
#872=VECTOR('',#871,1.);
#873=CARTESIAN_POINT('',(-20.5,0.,0.));
#874=LINE('',#873,#872);
#875=CARTESIAN_POINT('',(-20.5,16.7928932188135,0.));
#876=VERTEX_POINT('',#875);
#877=EDGE_CURVE('E665',#868,#876,#874,.T.);
#878=ORIENTED_EDGE('',*,*,#877,.T.);
#879=DIRECTION('',(0.707106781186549,0.707106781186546,0.));
#880=VECTOR('',#879,1.);
#881=CARTESIAN_POINT('',(-16.6464466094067,20.6464466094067,0.));
#882=LINE('',#881,#880);
#883=EDGE_CURVE('E667',#876,#826,#882,.T.);
#884=ORIENTED_EDGE('',*,*,#883,.T.);
#885=EDGE_LOOP('',(#830,#838,#846,#854,#862,#870,#878,#884));
#886=FACE_BOUND('',#885,.T.);
#887=ADVANCED_FACE('F839',(#776,#787,#798,#809,#820,#886),#765,.F.);
#888=DIRECTION('',(-0.707106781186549,-0.707106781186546,0.));
#889=VECTOR('',#888,1.);
#890=CARTESIAN_POINT('',(21.,-17.,12.5));
#891=LINE('',#890,#889);
#892=EDGE_CURVE('E1087',#662,#493,#891,.F.);
#893=ORIENTED_EDGE('',*,*,#892,.F.);
#894=ORIENTED_EDGE('',*,*,#663,.F.);
#895=DIRECTION('',(-0.707106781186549,-0.707106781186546,0.));
#896=VECTOR('',#895,1.);
#897=CARTESIAN_POINT('',(21.,-17.,0.500000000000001));
#898=LINE('',#897,#896);
#899=EDGE_CURVE('E707',#658,#497,#898,.F.);
#900=ORIENTED_EDGE('',*,*,#899,.T.);
#901=ORIENTED_EDGE('',*,*,#498,.F.);
#902=EDGE_LOOP('',(#893,#894,#900,#901));
#903=FACE_BOUND('',#902,.T.);
#904=ADVANCED_FACE('F844',(#903),#383,.F.);
#905=DIRECTION('',(0.707106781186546,-0.707106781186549,0.));
#906=VECTOR('',#905,1.);
#907=CARTESIAN_POINT('',(17.,21.,12.5));
#908=LINE('',#907,#906);
#909=EDGE_CURVE('E1082',#509,#544,#908,.F.);
#910=ORIENTED_EDGE('',*,*,#909,.F.);
#911=ORIENTED_EDGE('',*,*,#510,.F.);
#912=DIRECTION('',(0.707106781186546,-0.707106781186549,0.));
#913=VECTOR('',#912,1.);
#914=CARTESIAN_POINT('',(17.,21.,0.5));
#915=LINE('',#914,#913);
#916=EDGE_CURVE('E677',#505,#548,#915,.F.);
#917=ORIENTED_EDGE('',*,*,#916,.T.);
#918=ORIENTED_EDGE('',*,*,#549,.F.);
#919=EDGE_LOOP('',(#910,#911,#917,#918));
#920=FACE_BOUND('',#919,.T.);
#921=ADVANCED_FACE('F867',(#920),#361,.F.);
#922=DIRECTION('',(0.707106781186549,0.707106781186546,0.));
#923=VECTOR('',#922,1.);
#924=CARTESIAN_POINT('',(-21.,17.,12.5));
#925=LINE('',#924,#923);
#926=EDGE_CURVE('E1075',#560,#595,#925,.F.);
#927=ORIENTED_EDGE('',*,*,#926,.F.);
#928=ORIENTED_EDGE('',*,*,#561,.F.);
#929=DIRECTION('',(0.707106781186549,0.707106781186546,0.));
#930=VECTOR('',#929,1.);
#931=CARTESIAN_POINT('',(-21.,17.,0.5));
#932=LINE('',#931,#930);
#933=EDGE_CURVE('E687',#556,#599,#932,.F.);
#934=ORIENTED_EDGE('',*,*,#933,.T.);
#935=ORIENTED_EDGE('',*,*,#600,.F.);
#936=EDGE_LOOP('',(#927,#928,#934,#935));
#937=FACE_BOUND('',#936,.T.);
#938=ADVANCED_FACE('F872',(#937),#339,.F.);
#939=DIRECTION('',(-0.707106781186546,0.707106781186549,0.));
#940=VECTOR('',#939,1.);
#941=CARTESIAN_POINT('',(-17.,-21.,12.5));
#942=LINE('',#941,#940);
#943=EDGE_CURVE('E1091',#611,#646,#942,.F.);
#944=ORIENTED_EDGE('',*,*,#943,.F.);
#945=ORIENTED_EDGE('',*,*,#612,.F.);
#946=DIRECTION('',(-0.707106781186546,0.707106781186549,0.));
#947=VECTOR('',#946,1.);
#948=CARTESIAN_POINT('',(-17.,-21.,0.500000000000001));
#949=LINE('',#948,#947);
#950=EDGE_CURVE('E697',#607,#650,#949,.F.);
#951=ORIENTED_EDGE('',*,*,#950,.T.);
#952=ORIENTED_EDGE('',*,*,#651,.F.);
#953=EDGE_LOOP('',(#944,#945,#951,#952));
#954=FACE_BOUND('',#953,.T.);
#955=ADVANCED_FACE('F877',(#954),#405,.F.);
#956=CARTESIAN_POINT('',(-18.6464466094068,-18.6464466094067,0.));
#957=DIRECTION('',(0.500000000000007,0.500000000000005,0.707106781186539));
#958=DIRECTION('',(-0.707106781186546,0.707106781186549,0.));
#959=AXIS2_PLACEMENT_3D('',#956,#957,#958);
#960=PLANE('',#959);
#961=DIRECTION('',(0.28108463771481,0.678598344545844,-0.678598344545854));
#962=VECTOR('',#961,1.);
#963=CARTESIAN_POINT('',(-17.3160342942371,-21.7629742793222,1.26297427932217));
#964=LINE('',#963,#962);
#965=EDGE_CURVE('E750',#650,#860,#964,.T.);
#966=ORIENTED_EDGE('',*,*,#965,.F.);
#967=ORIENTED_EDGE('',*,*,#950,.F.);
#968=DIRECTION('',(0.678598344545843,0.281084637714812,-0.678598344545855));
#969=VECTOR('',#968,1.);
#970=CARTESIAN_POINT('',(-20.,-16.5857864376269,-0.500000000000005));
#971=LINE('',#970,#969);
#972=EDGE_CURVE('E753',#868,#607,#971,.F.);
#973=ORIENTED_EDGE('',*,*,#972,.F.);
#974=ORIENTED_EDGE('',*,*,#869,.F.);
#975=EDGE_LOOP('',(#966,#967,#973,#974));
#976=FACE_BOUND('',#975,.T.);
#977=ADVANCED_FACE('F882',(#976),#960,.F.);
#978=CARTESIAN_POINT('',(-21.,21.,0.5));
#979=DIRECTION('',(0.707106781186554,0.,0.707106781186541));
#980=DIRECTION('',(0.,-1.,0.));
#981=AXIS2_PLACEMENT_3D('',#978,#979,#980);
#982=PLANE('',#981);
#983=ORIENTED_EDGE('',*,*,#972,.T.);
#984=ORIENTED_EDGE('',*,*,#608,.F.);
#985=DIRECTION('',(0.678598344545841,-0.281084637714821,-0.678598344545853));
#986=VECTOR('',#985,1.);
#987=CARTESIAN_POINT('',(-21.7629742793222,17.3160342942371,1.26297427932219));
#988=LINE('',#987,#986);
#989=EDGE_CURVE('E747',#876,#599,#988,.F.);
#990=ORIENTED_EDGE('',*,*,#989,.F.);
#991=ORIENTED_EDGE('',*,*,#877,.F.);
#992=EDGE_LOOP('',(#983,#984,#990,#991));
#993=FACE_BOUND('',#992,.T.);
#994=ADVANCED_FACE('F908',(#993),#982,.F.);
#995=CARTESIAN_POINT('',(-21.,-21.,0.5));
#996=DIRECTION('',(0.,0.707106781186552,0.707106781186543));
#997=DIRECTION('',(1.,0.,0.));
#998=AXIS2_PLACEMENT_3D('',#995,#996,#997);
#999=PLANE('',#998);
#1000=ORIENTED_EDGE('',*,*,#965,.T.);
#1001=ORIENTED_EDGE('',*,*,#861,.F.);
#1002=DIRECTION('',(-0.281084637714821,0.678598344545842,-0.678598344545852));
#1003=VECTOR('',#1002,1.);
#1004=CARTESIAN_POINT('',(16.5857864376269,-20.,-0.499999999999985));
#1005=LINE('',#1004,#1003);
#1006=EDGE_CURVE('E744',#658,#852,#1005,.T.);
#1007=ORIENTED_EDGE('',*,*,#1006,.F.);
#1008=ORIENTED_EDGE('',*,*,#659,.F.);
#1009=EDGE_LOOP('',(#1000,#1001,#1007,#1008));
#1010=FACE_BOUND('',#1009,.T.);
#1011=ADVANCED_FACE('F904',(#1010),#999,.F.);
#1012=CARTESIAN_POINT('',(-18.6464466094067,18.6464466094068,0.));
#1013=DIRECTION('',(0.500000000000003,-0.500000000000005,0.707106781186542));
#1014=DIRECTION('',(0.707106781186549,0.707106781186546,0.));
#1015=AXIS2_PLACEMENT_3D('',#1012,#1013,#1014);
#1016=PLANE('',#1015);
#1017=ORIENTED_EDGE('',*,*,#989,.T.);
#1018=ORIENTED_EDGE('',*,*,#933,.F.);
#1019=DIRECTION('',(0.281084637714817,-0.678598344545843,-0.678598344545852));
#1020=VECTOR('',#1019,1.);
#1021=CARTESIAN_POINT('',(-16.5857864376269,20.,-0.499999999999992));
#1022=LINE('',#1021,#1020);
#1023=EDGE_CURVE('E741',#826,#556,#1022,.F.);
#1024=ORIENTED_EDGE('',*,*,#1023,.F.);
#1025=ORIENTED_EDGE('',*,*,#883,.F.);
#1026=EDGE_LOOP('',(#1017,#1018,#1024,#1025));
#1027=FACE_BOUND('',#1026,.T.);
#1028=ADVANCED_FACE('F900',(#1027),#1016,.F.);
#1029=CARTESIAN_POINT('',(18.6464466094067,-18.6464466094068,0.));
#1030=DIRECTION('',(-0.500000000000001,0.500000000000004,0.707106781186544));
#1031=DIRECTION('',(-0.707106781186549,-0.707106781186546,0.));
#1032=AXIS2_PLACEMENT_3D('',#1029,#1030,#1031);
#1033=PLANE('',#1032);
#1034=ORIENTED_EDGE('',*,*,#1006,.T.);
#1035=ORIENTED_EDGE('',*,*,#853,.F.);
#1036=DIRECTION('',(-0.678598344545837,0.281084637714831,-0.678598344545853));
#1037=VECTOR('',#1036,1.);
#1038=CARTESIAN_POINT('',(13.7517443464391,-13.9976742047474,-6.7482556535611));
#1039=LINE('',#1038,#1037);
#1040=EDGE_CURVE('E738',#497,#844,#1039,.T.);
#1041=ORIENTED_EDGE('',*,*,#1040,.F.);
#1042=ORIENTED_EDGE('',*,*,#899,.F.);
#1043=EDGE_LOOP('',(#1034,#1035,#1041,#1042));
#1044=FACE_BOUND('',#1043,.T.);
#1045=ADVANCED_FACE('F896',(#1044),#1033,.F.);
#1046=CARTESIAN_POINT('',(-21.,21.,0.5));
#1047=DIRECTION('',(0.,-0.707106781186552,0.707106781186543));
#1048=DIRECTION('',(-1.,0.,0.));
#1049=AXIS2_PLACEMENT_3D('',#1046,#1047,#1048);
#1050=PLANE('',#1049);
#1051=ORIENTED_EDGE('',*,*,#1023,.T.);
#1052=ORIENTED_EDGE('',*,*,#557,.F.);
#1053=DIRECTION('',(-0.281084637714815,-0.678598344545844,-0.678598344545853));
#1054=VECTOR('',#1053,1.);
#1055=CARTESIAN_POINT('',(13.9976742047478,13.7517443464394,-6.74825565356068));
#1056=LINE('',#1055,#1054);
#1057=EDGE_CURVE('E734',#828,#548,#1056,.F.);
#1058=ORIENTED_EDGE('',*,*,#1057,.F.);
#1059=ORIENTED_EDGE('',*,*,#829,.F.);
#1060=EDGE_LOOP('',(#1051,#1052,#1058,#1059));
#1061=FACE_BOUND('',#1060,.T.);
#1062=ADVANCED_FACE('F892',(#1061),#1050,.F.);
#1063=CARTESIAN_POINT('',(21.,21.,0.5));
#1064=DIRECTION('',(-0.707106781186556,0.,0.707106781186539));
#1065=DIRECTION('',(0.,1.,0.));
#1066=AXIS2_PLACEMENT_3D('',#1063,#1064,#1065);
#1067=PLANE('',#1066);
#1068=ORIENTED_EDGE('',*,*,#1040,.T.);
#1069=ORIENTED_EDGE('',*,*,#845,.F.);
#1070=DIRECTION('',(0.678598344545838,0.281084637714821,0.678598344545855));
#1071=VECTOR('',#1070,1.);
#1072=CARTESIAN_POINT('',(21.7629742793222,17.3160342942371,1.2629742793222));
#1073=LINE('',#1072,#1071);
#1074=EDGE_CURVE('E732',#505,#836,#1073,.F.);
#1075=ORIENTED_EDGE('',*,*,#1074,.F.);
#1076=ORIENTED_EDGE('',*,*,#506,.F.);
#1077=EDGE_LOOP('',(#1068,#1069,#1075,#1076));
#1078=FACE_BOUND('',#1077,.T.);
#1079=ADVANCED_FACE('F888',(#1078),#1067,.F.);
#1080=CARTESIAN_POINT('',(18.6464466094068,18.6464466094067,0.));
#1081=DIRECTION('',(-0.500000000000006,-0.500000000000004,0.707106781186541));
#1082=DIRECTION('',(0.707106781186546,-0.707106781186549,0.));
#1083=AXIS2_PLACEMENT_3D('',#1080,#1081,#1082);
#1084=PLANE('',#1083);
#1085=ORIENTED_EDGE('',*,*,#1057,.T.);
#1086=ORIENTED_EDGE('',*,*,#916,.F.);
#1087=ORIENTED_EDGE('',*,*,#1074,.T.);
#1088=ORIENTED_EDGE('',*,*,#837,.F.);
#1089=EDGE_LOOP('',(#1085,#1086,#1087,#1088));
#1090=FACE_BOUND('',#1089,.T.);
#1091=ADVANCED_FACE('F884',(#1090),#1084,.F.);
#1092=CARTESIAN_POINT('',(18.6464466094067,18.6464466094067,39.));
#1093=DIRECTION('',(0.500000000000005,0.500000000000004,0.707106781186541));
#1094=DIRECTION('',(0.707106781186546,-0.707106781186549,0.));
#1095=AXIS2_PLACEMENT_3D('',#1092,#1093,#1094);
#1096=PLANE('',#1095);
#1097=DIRECTION('',(-0.678598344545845,-0.281084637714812,0.678598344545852));
#1098=VECTOR('',#1097,1.);
#1099=CARTESIAN_POINT('',(17.2968635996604,15.4661106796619,42.2031364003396));
#1100=LINE('',#1099,#1098);
#1101=EDGE_CURVE('E772',#99,#733,#1100,.T.);
#1102=ORIENTED_EDGE('',*,*,#1101,.F.);
#1103=ORIENTED_EDGE('',*,*,#373,.F.);
#1104=DIRECTION('',(-0.281084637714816,-0.678598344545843,0.678598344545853));
#1105=VECTOR('',#1104,1.);
#1106=CARTESIAN_POINT('',(16.5857864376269,20.,39.5));
#1107=LINE('',#1106,#1105);
#1108=EDGE_CURVE('E735',#741,#323,#1107,.F.);
#1109=ORIENTED_EDGE('',*,*,#1108,.F.);
#1110=ORIENTED_EDGE('',*,*,#742,.F.);
#1111=EDGE_LOOP('',(#1102,#1103,#1109,#1110));
#1112=FACE_BOUND('',#1111,.T.);
#1113=ADVANCED_FACE('F887',(#1112),#1096,.T.);
#1114=CARTESIAN_POINT('',(0.,20.5,39.));
#1115=DIRECTION('',(0.,0.707106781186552,0.707106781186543));
#1116=DIRECTION('',(1.,0.,0.));
#1117=AXIS2_PLACEMENT_3D('',#1114,#1115,#1116);
#1118=PLANE('',#1117);
#1119=ORIENTED_EDGE('',*,*,#1108,.T.);
#1120=ORIENTED_EDGE('',*,*,#324,.F.);
#1121=DIRECTION('',(0.281084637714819,-0.678598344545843,0.678598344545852));
#1122=VECTOR('',#1121,1.);
#1123=CARTESIAN_POINT('',(-15.4661106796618,17.2968635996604,42.2031364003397));
#1124=LINE('',#1123,#1122);
#1125=EDGE_CURVE('E769',#749,#315,#1124,.F.);
#1126=ORIENTED_EDGE('',*,*,#1125,.F.);
#1127=ORIENTED_EDGE('',*,*,#750,.F.);
#1128=EDGE_LOOP('',(#1119,#1120,#1126,#1127));
#1129=FACE_BOUND('',#1128,.T.);
#1130=ADVANCED_FACE('F939',(#1129),#1118,.T.);
#1131=CARTESIAN_POINT('',(20.5,0.,39.));
#1132=DIRECTION('',(0.707106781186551,0.,0.707106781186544));
#1133=DIRECTION('',(0.,-1.,0.));
#1134=AXIS2_PLACEMENT_3D('',#1131,#1132,#1133);
#1135=PLANE('',#1134);
#1136=ORIENTED_EDGE('',*,*,#1101,.T.);
#1137=ORIENTED_EDGE('',*,*,#734,.F.);
#1138=DIRECTION('',(-0.678598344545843,0.281084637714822,0.67859834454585));
#1139=VECTOR('',#1138,1.);
#1140=CARTESIAN_POINT('',(20.,-16.5857864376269,39.5));
#1141=LINE('',#1140,#1139);
#1142=EDGE_CURVE('E766',#107,#725,#1141,.T.);
#1143=ORIENTED_EDGE('',*,*,#1142,.F.);
#1144=ORIENTED_EDGE('',*,*,#108,.F.);
#1145=EDGE_LOOP('',(#1136,#1137,#1143,#1144));
#1146=FACE_BOUND('',#1145,.T.);
#1147=ADVANCED_FACE('F935',(#1146),#1135,.T.);
#1148=CARTESIAN_POINT('',(-18.6464466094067,18.6464466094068,39.));
#1149=DIRECTION('',(-0.500000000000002,0.500000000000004,0.707106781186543));
#1150=DIRECTION('',(0.707106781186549,0.707106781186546,0.));
#1151=AXIS2_PLACEMENT_3D('',#1148,#1149,#1150);
#1152=PLANE('',#1151);
#1153=ORIENTED_EDGE('',*,*,#1125,.T.);
#1154=ORIENTED_EDGE('',*,*,#351,.F.);
#1155=DIRECTION('',(0.678598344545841,-0.281084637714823,0.678598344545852));
#1156=VECTOR('',#1155,1.);
#1157=CARTESIAN_POINT('',(-20.,16.5857864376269,39.5));
#1158=LINE('',#1157,#1156);
#1159=EDGE_CURVE('E763',#699,#251,#1158,.F.);
#1160=ORIENTED_EDGE('',*,*,#1159,.F.);
#1161=ORIENTED_EDGE('',*,*,#756,.F.);
#1162=EDGE_LOOP('',(#1153,#1154,#1160,#1161));
#1163=FACE_BOUND('',#1162,.T.);
#1164=ADVANCED_FACE('F931',(#1163),#1152,.T.);
#1165=CARTESIAN_POINT('',(18.6464466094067,-18.6464466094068,39.));
#1166=DIRECTION('',(0.500000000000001,-0.500000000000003,0.707106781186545));
#1167=DIRECTION('',(-0.707106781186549,-0.707106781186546,0.));
#1168=AXIS2_PLACEMENT_3D('',#1165,#1166,#1167);
#1169=PLANE('',#1168);
#1170=ORIENTED_EDGE('',*,*,#1142,.T.);
#1171=ORIENTED_EDGE('',*,*,#726,.F.);
#1172=DIRECTION('',(-0.281084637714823,0.678598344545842,0.678598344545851));
#1173=VECTOR('',#1172,1.);
#1174=CARTESIAN_POINT('',(15.4661106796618,-17.2968635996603,42.2031364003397));
#1175=LINE('',#1174,#1173);
#1176=EDGE_CURVE('E760',#171,#717,#1175,.T.);
#1177=ORIENTED_EDGE('',*,*,#1176,.F.);
#1178=ORIENTED_EDGE('',*,*,#395,.F.);
#1179=EDGE_LOOP('',(#1170,#1171,#1177,#1178));
#1180=FACE_BOUND('',#1179,.T.);
#1181=ADVANCED_FACE('F927',(#1180),#1169,.T.);
#1182=CARTESIAN_POINT('',(-20.5,0.,39.));
#1183=DIRECTION('',(-0.707106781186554,0.,0.707106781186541));
#1184=DIRECTION('',(0.,1.,0.));
#1185=AXIS2_PLACEMENT_3D('',#1182,#1183,#1184);
#1186=PLANE('',#1185);
#1187=ORIENTED_EDGE('',*,*,#1159,.T.);
#1188=ORIENTED_EDGE('',*,*,#252,.F.);
#1189=DIRECTION('',(0.678598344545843,0.281084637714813,0.678598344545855));
#1190=VECTOR('',#1189,1.);
#1191=CARTESIAN_POINT('',(-17.2968635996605,-15.4661106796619,42.2031364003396));
#1192=LINE('',#1191,#1190);
#1193=EDGE_CURVE('E757',#701,#243,#1192,.F.);
#1194=ORIENTED_EDGE('',*,*,#1193,.F.);
#1195=ORIENTED_EDGE('',*,*,#702,.F.);
#1196=EDGE_LOOP('',(#1187,#1188,#1194,#1195));
#1197=FACE_BOUND('',#1196,.T.);
#1198=ADVANCED_FACE('F923',(#1197),#1186,.T.);
#1199=CARTESIAN_POINT('',(0.,-20.5,39.));
#1200=DIRECTION('',(0.,-0.707106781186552,0.707106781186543));
#1201=DIRECTION('',(-1.,0.,0.));
#1202=AXIS2_PLACEMENT_3D('',#1199,#1200,#1201);
#1203=PLANE('',#1202);
#1204=ORIENTED_EDGE('',*,*,#1176,.T.);
#1205=ORIENTED_EDGE('',*,*,#718,.F.);
#1206=DIRECTION('',(-0.281084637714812,-0.678598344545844,-0.678598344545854));
#1207=VECTOR('',#1206,1.);
#1208=CARTESIAN_POINT('',(-15.4661106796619,-17.2968635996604,42.2031364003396));
#1209=LINE('',#1208,#1207);
#1210=EDGE_CURVE('E622',#179,#709,#1209,.F.);
#1211=ORIENTED_EDGE('',*,*,#1210,.F.);
#1212=ORIENTED_EDGE('',*,*,#180,.F.);
#1213=EDGE_LOOP('',(#1204,#1205,#1211,#1212));
#1214=FACE_BOUND('',#1213,.T.);
#1215=ADVANCED_FACE('F919',(#1214),#1203,.T.);
#1216=CARTESIAN_POINT('',(-18.6464466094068,-18.6464466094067,39.));
#1217=DIRECTION('',(-0.500000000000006,-0.500000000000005,0.70710678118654));
#1218=DIRECTION('',(-0.707106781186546,0.707106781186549,0.));
#1219=AXIS2_PLACEMENT_3D('',#1216,#1217,#1218);
#1220=PLANE('',#1219);
#1221=ORIENTED_EDGE('',*,*,#1193,.T.);
#1222=ORIENTED_EDGE('',*,*,#417,.F.);
#1223=ORIENTED_EDGE('',*,*,#1210,.T.);
#1224=ORIENTED_EDGE('',*,*,#710,.F.);
#1225=EDGE_LOOP('',(#1221,#1222,#1223,#1224));
#1226=FACE_BOUND('',#1225,.T.);
#1227=ADVANCED_FACE('F916',(#1226),#1220,.T.);
#1228=CARTESIAN_POINT('',(0.,0.,0.5));
#1229=DIRECTION('',(0.,0.,-1.));
#1230=DIRECTION('',(-1.,0.,0.));
#1231=AXIS2_PLACEMENT_3D('',#1228,#1229,#1230);
#1232=CONICAL_SURFACE('',#1231,14.,0.785398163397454);
#1233=ORIENTED_EDGE('',*,*,#817,.F.);
#1234=EDGE_LOOP('',(#1233));
#1235=FACE_BOUND('',#1234,.T.);
#1236=ORIENTED_EDGE('',*,*,#458,.F.);
#1237=EDGE_LOOP('',(#1236));
#1238=FACE_BOUND('',#1237,.T.);
#1239=ADVANCED_FACE('F825',(#1235,#1238),#1232,.F.);
#1240=CARTESIAN_POINT('',(0.,0.,-2.));
#1241=DIRECTION('',(0.,0.,-1.));
#1242=DIRECTION('',(-1.,0.,0.));
#1243=AXIS2_PLACEMENT_3D('',#1240,#1241,#1242);
#1244=PLANE('',#1243);
#1245=CARTESIAN_POINT('',(0.,0.,-2.));
#1246=DIRECTION('',(0.,0.,-1.));
#1247=DIRECTION('',(-1.,0.,0.));
#1248=AXIS2_PLACEMENT_3D('',#1245,#1246,#1247);
#1249=CIRCLE('',#1248,4.75);
#1250=CARTESIAN_POINT('',(-4.75,0.,-2.));
#1251=VERTEX_POINT('',#1250);
#1252=EDGE_CURVE('E615',#1251,#1251,#1249,.T.);
#1253=ORIENTED_EDGE('',*,*,#1252,.F.);
#1254=EDGE_LOOP('',(#1253));
#1255=FACE_BOUND('',#1254,.T.);
#1256=CARTESIAN_POINT('',(0.,0.,-2.));
#1257=DIRECTION('',(0.,0.,-1.));
#1258=DIRECTION('',(-1.,0.,0.));
#1259=AXIS2_PLACEMENT_3D('',#1256,#1257,#1258);
#1260=CIRCLE('',#1259,11.);
#1261=CARTESIAN_POINT('',(-11.,0.,-2.));
#1262=VERTEX_POINT('',#1261);
#1263=EDGE_CURVE('E619',#1262,#1262,#1260,.T.);
#1264=ORIENTED_EDGE('',*,*,#1263,.T.);
#1265=EDGE_LOOP('',(#1264));
#1266=FACE_BOUND('',#1265,.T.);
#1267=ADVANCED_FACE('F822',(#1255,#1266),#1244,.T.);
#1268=CARTESIAN_POINT('',(0.,0.,-2.));
#1269=DIRECTION('',(0.,0.,1.));
#1270=DIRECTION('',(1.,0.,0.));
#1271=AXIS2_PLACEMENT_3D('',#1268,#1269,#1270);
#1272=CYLINDRICAL_SURFACE('',#1271,11.);
#1273=ORIENTED_EDGE('',*,*,#1263,.F.);
#1274=EDGE_LOOP('',(#1273));
#1275=FACE_BOUND('',#1274,.T.);
#1276=ORIENTED_EDGE('',*,*,#469,.T.);
#1277=EDGE_LOOP('',(#1276));
#1278=FACE_BOUND('',#1277,.T.);
#1279=ADVANCED_FACE('F820',(#1275,#1278),#1272,.T.);
#1280=CARTESIAN_POINT('',(0.,0.,-2.));
#1281=DIRECTION('',(0.,0.,1.));
#1282=DIRECTION('',(1.,0.,0.));
#1283=AXIS2_PLACEMENT_3D('',#1280,#1281,#1282);
#1284=CYLINDRICAL_SURFACE('',#1283,4.75);
#1285=ORIENTED_EDGE('',*,*,#1252,.T.);
#1286=EDGE_LOOP('',(#1285));
#1287=FACE_BOUND('',#1286,.T.);
#1288=ORIENTED_EDGE('',*,*,#435,.T.);
#1289=EDGE_LOOP('',(#1288));
#1290=FACE_BOUND('',#1289,.T.);
#1291=ADVANCED_FACE('F816',(#1287,#1290),#1284,.F.);
#1292=CARTESIAN_POINT('',(0.,0.,-19.5));
#1293=DIRECTION('',(0.,0.,1.));
#1294=DIRECTION('',(1.,0.,0.));
#1295=AXIS2_PLACEMENT_3D('',#1292,#1293,#1294);
#1296=CYLINDRICAL_SURFACE('',#1295,2.5);
#1297=CARTESIAN_POINT('',(0.,0.,-19.25));
#1298=DIRECTION('',(0.,0.,-1.));
#1299=DIRECTION('',(-1.,0.,0.));
#1300=AXIS2_PLACEMENT_3D('',#1297,#1298,#1299);
#1301=CIRCLE('',#1300,2.5);
#1302=CARTESIAN_POINT('',(-1.5,2.,-19.25));
#1303=VERTEX_POINT('',#1302);
#1304=CARTESIAN_POINT('',(1.5,2.,-19.25));
#1305=VERTEX_POINT('',#1304);
#1306=EDGE_CURVE('E788',#1303,#1305,#1301,.F.);
#1307=ORIENTED_EDGE('',*,*,#1306,.T.);
#1308=DIRECTION('',(0.,0.,1.));
#1309=VECTOR('',#1308,1.);
#1310=CARTESIAN_POINT('',(1.5,2.,-19.5));
#1311=LINE('',#1310,#1309);
#1312=CARTESIAN_POINT('',(1.5,2.,-2.));
#1313=VERTEX_POINT('',#1312);
#1314=EDGE_CURVE('E609',#1305,#1313,#1311,.T.);
#1315=ORIENTED_EDGE('',*,*,#1314,.T.);
#1316=CARTESIAN_POINT('',(0.,0.,-2.));
#1317=DIRECTION('',(0.,0.,-1.));
#1318=DIRECTION('',(-1.,0.,0.));
#1319=AXIS2_PLACEMENT_3D('',#1316,#1317,#1318);
#1320=CIRCLE('',#1319,2.5);
#1321=CARTESIAN_POINT('',(-1.5,2.,-2.));
#1322=VERTEX_POINT('',#1321);
#1323=EDGE_CURVE('E798',#1322,#1313,#1320,.T.);
#1324=ORIENTED_EDGE('',*,*,#1323,.F.);
#1325=DIRECTION('',(0.,0.,1.));
#1326=VECTOR('',#1325,1.);
#1327=CARTESIAN_POINT('',(-1.5,2.,-19.5));
#1328=LINE('',#1327,#1326);
#1329=EDGE_CURVE('E605',#1322,#1303,#1328,.F.);
#1330=ORIENTED_EDGE('',*,*,#1329,.T.);
#1331=EDGE_LOOP('',(#1307,#1315,#1324,#1330));
#1332=FACE_BOUND('',#1331,.T.);
#1333=ORIENTED_EDGE('',*,*,#446,.T.);
#1334=EDGE_LOOP('',(#1333));
#1335=FACE_BOUND('',#1334,.T.);
#1336=ADVANCED_FACE('F812',(#1332,#1335),#1296,.T.);
#1337=CARTESIAN_POINT('',(0.,0.,-19.5));
#1338=DIRECTION('',(0.,0.,-1.));
#1339=DIRECTION('',(-1.,0.,0.));
#1340=AXIS2_PLACEMENT_3D('',#1337,#1338,#1339);
#1341=PLANE('',#1340);
#1342=DIRECTION('',(-1.,0.,0.));
#1343=VECTOR('',#1342,1.);
#1344=CARTESIAN_POINT('',(18.1030619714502,2.,-19.5));
#1345=LINE('',#1344,#1343);
#1346=CARTESIAN_POINT('',(1.0307764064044,2.,-19.5));
#1347=VERTEX_POINT('',#1346);
#1348=CARTESIAN_POINT('',(-1.0307764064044,2.,-19.5));
#1349=VERTEX_POINT('',#1348);
#1350=EDGE_CURVE('E599',#1347,#1349,#1345,.T.);
#1351=ORIENTED_EDGE('',*,*,#1350,.F.);
#1352=CARTESIAN_POINT('',(0.,0.,-19.5));
#1353=DIRECTION('',(0.,0.,-1.));
#1354=DIRECTION('',(-1.,0.,0.));
#1355=AXIS2_PLACEMENT_3D('',#1352,#1353,#1354);
#1356=CIRCLE('',#1355,2.25);
#1357=EDGE_CURVE('E785',#1347,#1349,#1356,.T.);
#1358=ORIENTED_EDGE('',*,*,#1357,.T.);
#1359=EDGE_LOOP('',(#1351,#1358));
#1360=FACE_BOUND('',#1359,.T.);
#1361=ADVANCED_FACE('F809',(#1360),#1341,.T.);
#1362=CARTESIAN_POINT('',(0.,0.,-19.5));
#1363=DIRECTION('',(0.,0.,1.));
#1364=DIRECTION('',(1.,0.,0.));
#1365=AXIS2_PLACEMENT_3D('',#1362,#1363,#1364);
#1366=CONICAL_SURFACE('',#1365,2.25,0.785398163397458);
#1367=CARTESIAN_POINT('',(5.1277129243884,2.,-16.2460523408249));
#1368=CARTESIAN_POINT('',(4.9710577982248,2.,-16.391956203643));
#1369=CARTESIAN_POINT('',(4.81399958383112,2.,-16.537433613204));
#1370=CARTESIAN_POINT('',(4.49869649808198,2.,-16.8271676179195));
#1371=CARTESIAN_POINT('',(4.34045136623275,2.,-16.9714239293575));
#1372=CARTESIAN_POINT('',(4.02140480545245,2.,-17.2592374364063));
#1373=CARTESIAN_POINT('',(3.86059336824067,2.,-17.402783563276));
#1374=CARTESIAN_POINT('',(3.53691771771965,2.,-17.68750952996));
#1375=CARTESIAN_POINT('',(3.37405377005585,2.,-17.8286896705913));
#1376=CARTESIAN_POINT('',(3.0782795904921,2.,-18.079716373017));
#1377=CARTESIAN_POINT('',(2.94589559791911,2.,-18.190180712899));
#1378=CARTESIAN_POINT('',(2.67855955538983,2.,-18.4080444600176));
#1379=CARTESIAN_POINT('',(2.54360680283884,2.,-18.515443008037));
#1380=CARTESIAN_POINT('',(2.27040869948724,2.,-18.7255838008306));
#1381=CARTESIAN_POINT('',(2.13216875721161,2.,-18.8283329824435));
#1382=CARTESIAN_POINT('',(1.92114649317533,2.,-18.9772123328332));
#1383=CARTESIAN_POINT('',(1.85021046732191,2.,-19.0259551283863));
#1384=CARTESIAN_POINT('',(1.706864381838,2.,-19.1212155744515));
#1385=CARTESIAN_POINT('',(1.63445451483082,2.,-19.1677335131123));
#1386=CARTESIAN_POINT('',(1.49464895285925,2.,-19.2537569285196));
#1387=CARTESIAN_POINT('',(1.42740834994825,2.,-19.2935131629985));
#1388=CARTESIAN_POINT('',(1.29126163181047,2.,-19.3700453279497));
#1389=CARTESIAN_POINT('',(1.22235589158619,2.,-19.4068219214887));
#1390=CARTESIAN_POINT('',(1.0826411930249,2.,-19.4765763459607));
#1391=CARTESIAN_POINT('',(1.011832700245,2.,-19.5095550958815));
#1392=CARTESIAN_POINT('',(0.868181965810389,2.,-19.570664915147));
#1393=CARTESIAN_POINT('',(0.795340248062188,2.,-19.5987972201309));
#1394=CARTESIAN_POINT('',(0.604485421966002,2.,-19.6635217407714));
#1395=CARTESIAN_POINT('',(0.484799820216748,2.,-19.695542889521));
#1396=CARTESIAN_POINT('',(0.302753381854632,2.,-19.7280988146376));
#1397=CARTESIAN_POINT('',(0.241737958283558,2.,-19.7363706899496));
#1398=CARTESIAN_POINT('',(0.119195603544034,2.,-19.7473781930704));
#1399=CARTESIAN_POINT('',(0.0576687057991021,2.,-19.7501141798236));
#1400=CARTESIAN_POINT('',(-0.0655765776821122,2.,-19.7498780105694));
#1401=CARTESIAN_POINT('',(-0.127294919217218,2.,-19.7468868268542));
#1402=CARTESIAN_POINT('',(-0.250204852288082,2.,-19.7353394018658));
#1403=CARTESIAN_POINT('',(-0.311396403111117,2.,-19.7267827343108));
#1404=CARTESIAN_POINT('',(-0.433025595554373,2.,-19.7045363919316));
#1405=CARTESIAN_POINT('',(-0.493460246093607,2.,-19.6908305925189));
#1406=CARTESIAN_POINT('',(-0.613115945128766,2.,-19.6589271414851));
#1407=CARTESIAN_POINT('',(-0.672336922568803,2.,-19.640729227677));
#1408=CARTESIAN_POINT('',(-0.858780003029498,2.,-19.5767420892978));
#1409=CARTESIAN_POINT('',(-0.983542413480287,2.,-19.5237856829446));
#1410=CARTESIAN_POINT('',(-1.22729947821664,2.,-19.4058946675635));
#1411=CARTESIAN_POINT('',(-1.34628211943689,2.,-19.3409363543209));
#1412=CARTESIAN_POINT('',(-1.5810851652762,2.,-19.2023027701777));
#1413=CARTESIAN_POINT('',(-1.69684431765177,2.,-19.1285251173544));
#1414=CARTESIAN_POINT('',(-1.92459751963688,2.,-18.975657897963));
#1415=CARTESIAN_POINT('',(-2.03659485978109,2.,-18.8965731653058));
#1416=CARTESIAN_POINT('',(-2.28392033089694,2.,-18.7155978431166));
#1417=CARTESIAN_POINT('',(-2.41852567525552,2.,-18.6127253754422));
#1418=CARTESIAN_POINT('',(-2.68475669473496,2.,-18.4031793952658));
#1419=CARTESIAN_POINT('',(-2.8163818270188,2.,-18.2965051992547));
#1420=CARTESIAN_POINT('',(-3.07756548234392,2.,-18.0803904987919));
#1421=CARTESIAN_POINT('',(-3.20712169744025,2.,-17.9709472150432));
#1422=CARTESIAN_POINT('',(-3.46458080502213,2.,-17.7501316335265));
#1423=CARTESIAN_POINT('',(-3.59248364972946,2.,-17.6387592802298));
#1424=CARTESIAN_POINT('',(-3.83890922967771,2.,-17.4217155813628));
#1425=CARTESIAN_POINT('',(-3.95751039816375,2.,-17.3161331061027));
#1426=CARTESIAN_POINT('',(-4.19382980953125,2.,-17.1039799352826));
#1427=CARTESIAN_POINT('',(-4.31154803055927,2.,-16.9974092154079));
#1428=CARTESIAN_POINT('',(-4.54600690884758,2.,-16.783728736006));
#1429=CARTESIAN_POINT('',(-4.66274917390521,2.,-16.676620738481));
#1430=CARTESIAN_POINT('',(-4.89564229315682,2.,-16.4617747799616));
#1431=CARTESIAN_POINT('',(-5.01179317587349,2.,-16.3540368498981));
#1432=CARTESIAN_POINT('',(-5.1277129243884,2.,-16.2460523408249));
#1433=B_SPLINE_CURVE_WITH_KNOTS('',3,(#1367,#1368,#1369,#1370,#1371,#1372,#1373,#1374,#1375,
#1376,#1377,#1378,#1379,#1380,#1381,#1382,#1383,#1384,#1385,#1386,#1387,#1388,#1389,#1390,#1391,
#1392,#1393,#1394,#1395,#1396,#1397,#1398,#1399,#1400,#1401,#1402,#1403,#1404,#1405,#1406,#1407,
#1408,#1409,#1410,#1411,#1412,#1413,#1414,#1415,#1416,#1417,#1418,#1419,#1420,#1421,#1422,#1423,
#1424,#1425,#1426,#1427,#1428,#1429,#1430,#1431,#1432),.UNSPECIFIED.,.F.,.F.,(4,2,2,2,2,2,2,2,2,
2,2,2,2,2,2,2,2,2,2,2,2,2,2,2,2,2,2,2,2,2,2,2,4),(0.,0.642235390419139,1.28461611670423,
1.93127854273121,2.57785811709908,3.09507724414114,3.6124399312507,4.12900338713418,
4.38717784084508,4.64531876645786,4.87960181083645,5.11383257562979,5.34800654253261,
5.58212071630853,5.95215764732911,6.13666481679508,6.32116002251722,6.50626925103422,
6.69139265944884,6.87710068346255,7.06281954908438,7.46831055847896,7.87461115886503,
8.28619594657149,8.69741080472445,9.20554759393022,9.71377620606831,10.2225369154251,
10.7313122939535,11.207672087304,11.684043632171,12.1593388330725,12.6346108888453),.UNSPECIFIED.);
#1434=EDGE_CURVE('E797',#1305,#1347,#1433,.T.);
#1435=ORIENTED_EDGE('',*,*,#1434,.F.);
#1436=ORIENTED_EDGE('',*,*,#1306,.F.);
#1437=EDGE_CURVE('E791',#1349,#1303,#1433,.T.);
#1438=ORIENTED_EDGE('',*,*,#1437,.F.);
#1439=ORIENTED_EDGE('',*,*,#1357,.F.);
#1440=EDGE_LOOP('',(#1435,#1436,#1438,#1439));
#1441=FACE_BOUND('',#1440,.T.);
#1442=ADVANCED_FACE('F37',(#1441),#1366,.T.);
#1443=CARTESIAN_POINT('',(0.,0.,-2.));
#1444=DIRECTION('',(0.,0.,-1.));
#1445=DIRECTION('',(-1.,0.,0.));
#1446=AXIS2_PLACEMENT_3D('',#1443,#1444,#1445);
#1447=PLANE('',#1446);
#1448=ORIENTED_EDGE('',*,*,#1323,.T.);
#1449=DIRECTION('',(1.,0.,0.));
#1450=VECTOR('',#1449,1.);
#1451=CARTESIAN_POINT('',(18.1030619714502,2.,-2.));
#1452=LINE('',#1451,#1450);
#1453=EDGE_CURVE('E602',#1322,#1313,#1452,.T.);
#1454=ORIENTED_EDGE('',*,*,#1453,.F.);
#1455=EDGE_LOOP('',(#1448,#1454));
#1456=FACE_BOUND('',#1455,.T.);
#1457=ADVANCED_FACE('F806',(#1456),#1447,.T.);
#1458=CARTESIAN_POINT('',(18.1030619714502,2.,26.4894554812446));
#1459=DIRECTION('',(0.,-1.,0.));
#1460=DIRECTION('',(0.,0.,-1.));
#1461=AXIS2_PLACEMENT_3D('',#1458,#1459,#1460);
#1462=PLANE('',#1461);
#1463=ORIENTED_EDGE('',*,*,#1434,.T.);
#1464=ORIENTED_EDGE('',*,*,#1350,.T.);
#1465=ORIENTED_EDGE('',*,*,#1437,.T.);
#1466=ORIENTED_EDGE('',*,*,#1329,.F.);
#1467=ORIENTED_EDGE('',*,*,#1453,.T.);
#1468=ORIENTED_EDGE('',*,*,#1314,.F.);
#1469=EDGE_LOOP('',(#1463,#1464,#1465,#1466,#1467,#1468));
#1470=FACE_BOUND('',#1469,.T.);
#1471=ADVANCED_FACE('F800',(#1470),#1462,.F.);
#1472=CARTESIAN_POINT('',(15.35,15.35,12.));
#1473=DIRECTION('',(0.,0.,-1.));
#1474=DIRECTION('',(-1.,0.,0.));
#1475=AXIS2_PLACEMENT_3D('',#1472,#1473,#1474);
#1476=CYLINDRICAL_SURFACE('',#1475,1.5);
#1477=CARTESIAN_POINT('',(15.35,15.35,12.));
#1478=DIRECTION('',(0.,0.,-1.));
#1479=DIRECTION('',(-1.,0.,0.));
#1480=AXIS2_PLACEMENT_3D('',#1477,#1478,#1479);
#1481=CIRCLE('',#1480,1.5);
#1482=CARTESIAN_POINT('',(13.85,15.35,12.));
#1483=VERTEX_POINT('',#1482);
#1484=EDGE_CURVE('E596',#1483,#1483,#1481,.T.);
#1485=ORIENTED_EDGE('',*,*,#1484,.F.);
#1486=EDGE_LOOP('',(#1485));
#1487=FACE_BOUND('',#1486,.T.);
#1488=ORIENTED_EDGE('',*,*,#806,.T.);
#1489=EDGE_LOOP('',(#1488));
#1490=FACE_BOUND('',#1489,.T.);
#1491=ADVANCED_FACE('F805',(#1487,#1490),#1476,.F.);
#1492=CARTESIAN_POINT('',(15.35,15.35,12.));
#1493=DIRECTION('',(0.,0.,-1.));
#1494=DIRECTION('',(-1.,0.,0.));
#1495=AXIS2_PLACEMENT_3D('',#1492,#1493,#1494);
#1496=PLANE('',#1495);
#1497=ORIENTED_EDGE('',*,*,#1484,.T.);
#1498=EDGE_LOOP('',(#1497));
#1499=FACE_BOUND('',#1498,.T.);
#1500=ADVANCED_FACE('F1516',(#1499),#1496,.T.);
#1501=CARTESIAN_POINT('',(-15.3500000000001,15.3499999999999,12.));
#1502=DIRECTION('',(0.,0.,-1.));
#1503=DIRECTION('',(-1.,0.,0.));
#1504=AXIS2_PLACEMENT_3D('',#1501,#1502,#1503);
#1505=CYLINDRICAL_SURFACE('',#1504,1.5);
#1506=CARTESIAN_POINT('',(-15.3500000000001,15.3499999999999,12.));
#1507=DIRECTION('',(0.,0.,-1.));
#1508=DIRECTION('',(0.,-1.,0.));
#1509=AXIS2_PLACEMENT_3D('',#1506,#1507,#1508);
#1510=CIRCLE('',#1509,1.5);
#1511=CARTESIAN_POINT('',(-15.3500000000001,13.8499999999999,12.));
#1512=VERTEX_POINT('',#1511);
#1513=EDGE_CURVE('E590',#1512,#1512,#1510,.T.);
#1514=ORIENTED_EDGE('',*,*,#1513,.F.);
#1515=EDGE_LOOP('',(#1514));
#1516=FACE_BOUND('',#1515,.T.);
#1517=ORIENTED_EDGE('',*,*,#795,.T.);
#1518=EDGE_LOOP('',(#1517));
#1519=FACE_BOUND('',#1518,.T.);
#1520=ADVANCED_FACE('F1509',(#1516,#1519),#1505,.F.);
#1521=CARTESIAN_POINT('',(-15.3500000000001,15.3499999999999,12.));
#1522=DIRECTION('',(0.,0.,-1.));
#1523=DIRECTION('',(0.,-1.,0.));
#1524=AXIS2_PLACEMENT_3D('',#1521,#1522,#1523);
#1525=PLANE('',#1524);
#1526=ORIENTED_EDGE('',*,*,#1513,.T.);
#1527=EDGE_LOOP('',(#1526));
#1528=FACE_BOUND('',#1527,.T.);
#1529=ADVANCED_FACE('F1501',(#1528),#1525,.T.);
#1530=CARTESIAN_POINT('',(-15.35,-15.35,12.));
#1531=DIRECTION('',(0.,0.,-1.));
#1532=DIRECTION('',(-1.,0.,0.));
#1533=AXIS2_PLACEMENT_3D('',#1530,#1531,#1532);
#1534=CYLINDRICAL_SURFACE('',#1533,1.5);
#1535=CARTESIAN_POINT('',(-15.35,-15.35,12.));
#1536=DIRECTION('',(0.,0.,-1.));
#1537=DIRECTION('',(1.,0.,0.));
#1538=AXIS2_PLACEMENT_3D('',#1535,#1536,#1537);
#1539=CIRCLE('',#1538,1.5);
#1540=CARTESIAN_POINT('',(-13.85,-15.35,12.));
#1541=VERTEX_POINT('',#1540);
#1542=EDGE_CURVE('E584',#1541,#1541,#1539,.T.);
#1543=ORIENTED_EDGE('',*,*,#1542,.F.);
#1544=EDGE_LOOP('',(#1543));
#1545=FACE_BOUND('',#1544,.T.);
#1546=ORIENTED_EDGE('',*,*,#784,.T.);
#1547=EDGE_LOOP('',(#1546));
#1548=FACE_BOUND('',#1547,.T.);
#1549=ADVANCED_FACE('F1493',(#1545,#1548),#1534,.F.);
#1550=CARTESIAN_POINT('',(-15.35,-15.35,12.));
#1551=DIRECTION('',(0.,0.,-1.));
#1552=DIRECTION('',(1.,0.,0.));
#1553=AXIS2_PLACEMENT_3D('',#1550,#1551,#1552);
#1554=PLANE('',#1553);
#1555=ORIENTED_EDGE('',*,*,#1542,.T.);
#1556=EDGE_LOOP('',(#1555));
#1557=FACE_BOUND('',#1556,.T.);
#1558=ADVANCED_FACE('F1485',(#1557),#1554,.T.);
#1559=CARTESIAN_POINT('',(15.3500000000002,-15.3499999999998,12.));
#1560=DIRECTION('',(0.,0.,-1.));
#1561=DIRECTION('',(-1.,0.,0.));
#1562=AXIS2_PLACEMENT_3D('',#1559,#1560,#1561);
#1563=CYLINDRICAL_SURFACE('',#1562,1.5);
#1564=CARTESIAN_POINT('',(15.3500000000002,-15.3499999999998,12.));
#1565=DIRECTION('',(0.,0.,-1.));
#1566=DIRECTION('',(0.,1.,0.));
#1567=AXIS2_PLACEMENT_3D('',#1564,#1565,#1566);
#1568=CIRCLE('',#1567,1.5);
#1569=CARTESIAN_POINT('',(15.3500000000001,-13.8499999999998,12.));
#1570=VERTEX_POINT('',#1569);
#1571=EDGE_CURVE('E578',#1570,#1570,#1568,.T.);
#1572=ORIENTED_EDGE('',*,*,#1571,.F.);
#1573=EDGE_LOOP('',(#1572));
#1574=FACE_BOUND('',#1573,.T.);
#1575=ORIENTED_EDGE('',*,*,#773,.T.);
#1576=EDGE_LOOP('',(#1575));
#1577=FACE_BOUND('',#1576,.T.);
#1578=ADVANCED_FACE('F1477',(#1574,#1577),#1563,.F.);
#1579=CARTESIAN_POINT('',(15.3500000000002,-15.3499999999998,12.));
#1580=DIRECTION('',(0.,0.,-1.));
#1581=DIRECTION('',(0.,1.,0.));
#1582=AXIS2_PLACEMENT_3D('',#1579,#1580,#1581);
#1583=PLANE('',#1582);
#1584=ORIENTED_EDGE('',*,*,#1571,.T.);
#1585=EDGE_LOOP('',(#1584));
#1586=FACE_BOUND('',#1585,.T.);
#1587=ADVANCED_FACE('F1469',(#1586),#1583,.T.);
#1588=CARTESIAN_POINT('',(-17.5857864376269,-17.5857864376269,0.));
#1589=DIRECTION('',(0.707106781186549,0.707106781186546,0.));
#1590=DIRECTION('',(-0.707106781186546,0.707106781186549,0.));
#1591=AXIS2_PLACEMENT_3D('',#1588,#1589,#1590);
#1592=PLANE('',#1591);
#1593=DIRECTION('',(0.707106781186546,-0.707106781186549,0.));
#1594=VECTOR('',#1593,1.);
#1595=CARTESIAN_POINT('',(-11.598846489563,-23.5727263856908,12.5));
#1596=LINE('',#1595,#1594);
#1597=EDGE_CURVE('E560',#619,#638,#1596,.T.);
#1598=ORIENTED_EDGE('',*,*,#1597,.T.);
#1599=DIRECTION('',(0.,0.,-1.));
#1600=VECTOR('',#1599,1.);
#1601=CARTESIAN_POINT('',(-14.1715728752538,-21.,39.));
#1602=LINE('',#1601,#1600);
#1603=EDGE_CURVE('E1089',#131,#638,#1602,.T.);
#1604=ORIENTED_EDGE('',*,*,#1603,.F.);
#1605=DIRECTION('',(-0.707106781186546,0.707106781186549,0.));
#1606=VECTOR('',#1605,1.);
#1607=CARTESIAN_POINT('',(-11.598846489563,-23.5727263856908,26.5));
#1608=LINE('',#1607,#1606);
#1609=EDGE_CURVE('E557',#131,#227,#1608,.T.);
#1610=ORIENTED_EDGE('',*,*,#1609,.T.);
#1611=DIRECTION('',(0.,0.,1.));
#1612=VECTOR('',#1611,1.);
#1613=CARTESIAN_POINT('',(-21.,-14.1715728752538,39.));
#1614=LINE('',#1613,#1612);
#1615=EDGE_CURVE('E575',#619,#227,#1614,.T.);
#1616=ORIENTED_EDGE('',*,*,#1615,.F.);
#1617=EDGE_LOOP('',(#1598,#1604,#1610,#1616));
#1618=FACE_BOUND('',#1617,.T.);
#1619=ADVANCED_FACE('F1462',(#1618),#1592,.F.);
#1620=CARTESIAN_POINT('',(-11.598846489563,-23.5727263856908,26.5));
#1621=DIRECTION('',(0.,0.,1.));
#1622=DIRECTION('',(1.,0.,0.));
#1623=AXIS2_PLACEMENT_3D('',#1620,#1621,#1622);
#1624=PLANE('',#1623);
#1625=ORIENTED_EDGE('',*,*,#1609,.F.);
#1626=ORIENTED_EDGE('',*,*,#132,.F.);
#1627=ORIENTED_EDGE('',*,*,#410,.T.);
#1628=ORIENTED_EDGE('',*,*,#236,.F.);
#1629=EDGE_LOOP('',(#1625,#1626,#1627,#1628));
#1630=FACE_BOUND('',#1629,.T.);
#1631=ADVANCED_FACE('F1455',(#1630),#1624,.F.);
#1632=CARTESIAN_POINT('',(-11.598846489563,-23.5727263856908,12.5));
#1633=DIRECTION('',(0.,0.,-1.));
#1634=DIRECTION('',(-1.,0.,0.));
#1635=AXIS2_PLACEMENT_3D('',#1632,#1633,#1634);
#1636=PLANE('',#1635);
#1637=ORIENTED_EDGE('',*,*,#943,.T.);
#1638=ORIENTED_EDGE('',*,*,#647,.F.);
#1639=ORIENTED_EDGE('',*,*,#1597,.F.);
#1640=ORIENTED_EDGE('',*,*,#620,.F.);
#1641=EDGE_LOOP('',(#1637,#1638,#1639,#1640));
#1642=FACE_BOUND('',#1641,.T.);
#1643=ADVANCED_FACE('F1447',(#1642),#1636,.F.);
#1644=CARTESIAN_POINT('',(17.5857864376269,-17.5857864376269,0.));
#1645=DIRECTION('',(-0.707106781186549,0.707106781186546,0.));
#1646=DIRECTION('',(-0.707106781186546,-0.707106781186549,0.));
#1647=AXIS2_PLACEMENT_3D('',#1644,#1645,#1646);
#1648=PLANE('',#1647);
#1649=DIRECTION('',(-0.707106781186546,-0.707106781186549,0.));
#1650=VECTOR('',#1649,1.);
#1651=CARTESIAN_POINT('',(23.5727263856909,-11.5988464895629,26.5));
#1652=LINE('',#1651,#1650);
#1653=EDGE_CURVE('E537',#59,#155,#1652,.T.);
#1654=ORIENTED_EDGE('',*,*,#1653,.T.);
#1655=DIRECTION('',(0.,0.,1.));
#1656=VECTOR('',#1655,1.);
#1657=CARTESIAN_POINT('',(14.1715728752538,-21.,39.));
#1658=LINE('',#1657,#1656);
#1659=EDGE_CURVE('E1084',#670,#155,#1658,.T.);
#1660=ORIENTED_EDGE('',*,*,#1659,.F.);
#1661=DIRECTION('',(0.707106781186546,0.707106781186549,0.));
#1662=VECTOR('',#1661,1.);
#1663=CARTESIAN_POINT('',(23.5727263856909,-11.5988464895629,12.5));
#1664=LINE('',#1663,#1662);
#1665=EDGE_CURVE('E540',#670,#485,#1664,.T.);
#1666=ORIENTED_EDGE('',*,*,#1665,.T.);
#1667=DIRECTION('',(0.,0.,-1.));
#1668=VECTOR('',#1667,1.);
#1669=CARTESIAN_POINT('',(21.,-14.1715728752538,39.));
#1670=LINE('',#1669,#1668);
#1671=EDGE_CURVE('E555',#59,#485,#1670,.T.);
#1672=ORIENTED_EDGE('',*,*,#1671,.F.);
#1673=EDGE_LOOP('',(#1654,#1660,#1666,#1672));
#1674=FACE_BOUND('',#1673,.T.);
#1675=ADVANCED_FACE('F1439',(#1674),#1648,.F.);
#1676=CARTESIAN_POINT('',(23.5727263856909,-11.5988464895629,26.5));
#1677=DIRECTION('',(0.,0.,1.));
#1678=DIRECTION('',(1.,0.,0.));
#1679=AXIS2_PLACEMENT_3D('',#1676,#1677,#1678);
#1680=PLANE('',#1679);
#1681=ORIENTED_EDGE('',*,*,#388,.T.);
#1682=ORIENTED_EDGE('',*,*,#164,.F.);
#1683=ORIENTED_EDGE('',*,*,#1653,.F.);
#1684=ORIENTED_EDGE('',*,*,#60,.F.);
#1685=EDGE_LOOP('',(#1681,#1682,#1683,#1684));
#1686=FACE_BOUND('',#1685,.T.);
#1687=ADVANCED_FACE('F1431',(#1686),#1680,.F.);
#1688=CARTESIAN_POINT('',(23.5727263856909,-11.5988464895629,12.5));
#1689=DIRECTION('',(0.,0.,-1.));
#1690=DIRECTION('',(-1.,0.,0.));
#1691=AXIS2_PLACEMENT_3D('',#1688,#1689,#1690);
#1692=PLANE('',#1691);
#1693=ORIENTED_EDGE('',*,*,#1665,.F.);
#1694=ORIENTED_EDGE('',*,*,#671,.F.);
#1695=ORIENTED_EDGE('',*,*,#892,.T.);
#1696=ORIENTED_EDGE('',*,*,#494,.F.);
#1697=EDGE_LOOP('',(#1693,#1694,#1695,#1696));
#1698=FACE_BOUND('',#1697,.T.);
#1699=ADVANCED_FACE('F1423',(#1698),#1692,.F.);
#1700=CARTESIAN_POINT('',(17.5857864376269,17.5857864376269,0.));
#1701=DIRECTION('',(-0.707106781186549,-0.707106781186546,0.));
#1702=DIRECTION('',(0.707106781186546,-0.707106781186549,0.));
#1703=AXIS2_PLACEMENT_3D('',#1700,#1701,#1702);
#1704=PLANE('',#1703);
#1705=DIRECTION('',(-0.707106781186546,0.707106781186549,0.));
#1706=VECTOR('',#1705,1.);
#1707=CARTESIAN_POINT('',(11.598846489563,23.5727263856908,12.5));
#1708=LINE('',#1707,#1706);
#1709=EDGE_CURVE('E522',#517,#536,#1708,.T.);
#1710=ORIENTED_EDGE('',*,*,#1709,.T.);
#1711=DIRECTION('',(0.,0.,-1.));
#1712=VECTOR('',#1711,1.);
#1713=CARTESIAN_POINT('',(14.1715728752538,21.,39.));
#1714=LINE('',#1713,#1712);
#1715=EDGE_CURVE('E1079',#275,#536,#1714,.T.);
#1716=ORIENTED_EDGE('',*,*,#1715,.F.);
#1717=DIRECTION('',(0.707106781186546,-0.707106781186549,0.));
#1718=VECTOR('',#1717,1.);
#1719=CARTESIAN_POINT('',(11.598846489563,23.5727263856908,26.5));
#1720=LINE('',#1719,#1718);
#1721=EDGE_CURVE('E519',#275,#83,#1720,.T.);
#1722=ORIENTED_EDGE('',*,*,#1721,.T.);
#1723=DIRECTION('',(0.,0.,1.));
#1724=VECTOR('',#1723,1.);
#1725=CARTESIAN_POINT('',(21.,14.1715728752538,39.));
#1726=LINE('',#1725,#1724);
#1727=EDGE_CURVE('E535',#517,#83,#1726,.T.);
#1728=ORIENTED_EDGE('',*,*,#1727,.F.);
#1729=EDGE_LOOP('',(#1710,#1716,#1722,#1728));
#1730=FACE_BOUND('',#1729,.T.);
#1731=ADVANCED_FACE('F1415',(#1730),#1704,.F.);
#1732=CARTESIAN_POINT('',(11.598846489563,23.5727263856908,26.5));
#1733=DIRECTION('',(0.,0.,1.));
#1734=DIRECTION('',(1.,0.,0.));
#1735=AXIS2_PLACEMENT_3D('',#1732,#1733,#1734);
#1736=PLANE('',#1735);
#1737=ORIENTED_EDGE('',*,*,#1721,.F.);
#1738=ORIENTED_EDGE('',*,*,#276,.F.);
#1739=ORIENTED_EDGE('',*,*,#366,.T.);
#1740=ORIENTED_EDGE('',*,*,#92,.F.);
#1741=EDGE_LOOP('',(#1737,#1738,#1739,#1740));
#1742=FACE_BOUND('',#1741,.T.);
#1743=ADVANCED_FACE('F1408',(#1742),#1736,.F.);
#1744=CARTESIAN_POINT('',(11.598846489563,23.5727263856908,12.5));
#1745=DIRECTION('',(0.,0.,-1.));
#1746=DIRECTION('',(-1.,0.,0.));
#1747=AXIS2_PLACEMENT_3D('',#1744,#1745,#1746);
#1748=PLANE('',#1747);
#1749=ORIENTED_EDGE('',*,*,#909,.T.);
#1750=ORIENTED_EDGE('',*,*,#545,.F.);
#1751=ORIENTED_EDGE('',*,*,#1709,.F.);
#1752=ORIENTED_EDGE('',*,*,#518,.F.);
#1753=EDGE_LOOP('',(#1749,#1750,#1751,#1752));
#1754=FACE_BOUND('',#1753,.T.);
#1755=ADVANCED_FACE('F1401',(#1754),#1748,.F.);
#1756=CARTESIAN_POINT('',(-17.5857864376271,17.5857864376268,0.));
#1757=DIRECTION('',(0.707106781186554,-0.707106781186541,0.));
#1758=DIRECTION('',(0.707106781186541,0.707106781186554,0.));
#1759=AXIS2_PLACEMENT_3D('',#1756,#1757,#1758);
#1760=PLANE('',#1759);
#1761=DIRECTION('',(-0.707106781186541,-0.707106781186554,0.));
#1762=VECTOR('',#1761,1.);
#1763=CARTESIAN_POINT('',(-23.572726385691,11.5988464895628,12.5));
#1764=LINE('',#1763,#1762);
#1765=EDGE_CURVE('E504',#568,#587,#1764,.T.);
#1766=ORIENTED_EDGE('',*,*,#1765,.T.);
#1767=DIRECTION('',(0.,0.,-1.));
#1768=VECTOR('',#1767,1.);
#1769=CARTESIAN_POINT('',(-21.,14.1715728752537,39.));
#1770=LINE('',#1769,#1768);
#1771=EDGE_CURVE('E44',#203,#587,#1770,.T.);
#1772=ORIENTED_EDGE('',*,*,#1771,.F.);
#1773=DIRECTION('',(0.707106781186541,0.707106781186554,0.));
#1774=VECTOR('',#1773,1.);
#1775=CARTESIAN_POINT('',(-23.572726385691,11.5988464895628,26.5));
#1776=LINE('',#1775,#1774);
#1777=EDGE_CURVE('E494',#203,#299,#1776,.T.);
#1778=ORIENTED_EDGE('',*,*,#1777,.T.);
#1779=DIRECTION('',(0.,0.,1.));
#1780=VECTOR('',#1779,1.);
#1781=CARTESIAN_POINT('',(-14.1715728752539,21.,39.));
#1782=LINE('',#1781,#1780);
#1783=EDGE_CURVE('E517',#568,#299,#1782,.T.);
#1784=ORIENTED_EDGE('',*,*,#1783,.F.);
#1785=EDGE_LOOP('',(#1766,#1772,#1778,#1784));
#1786=FACE_BOUND('',#1785,.T.);
#1787=ADVANCED_FACE('F1072',(#1786),#1760,.F.);
#1788=CARTESIAN_POINT('',(-23.572726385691,11.5988464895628,26.5));
#1789=DIRECTION('',(0.,0.,1.));
#1790=DIRECTION('',(1.,0.,0.));
#1791=AXIS2_PLACEMENT_3D('',#1788,#1789,#1790);
#1792=PLANE('',#1791);
#1793=ORIENTED_EDGE('',*,*,#1777,.F.);
#1794=ORIENTED_EDGE('',*,*,#204,.F.);
#1795=ORIENTED_EDGE('',*,*,#344,.T.);
#1796=ORIENTED_EDGE('',*,*,#308,.F.);
#1797=EDGE_LOOP('',(#1793,#1794,#1795,#1796));
#1798=FACE_BOUND('',#1797,.T.);
#1799=ADVANCED_FACE('F1068',(#1798),#1792,.F.);
#1800=CARTESIAN_POINT('',(-23.572726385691,11.5988464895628,12.5));
#1801=DIRECTION('',(0.,0.,-1.));
#1802=DIRECTION('',(-1.,0.,0.));
#1803=AXIS2_PLACEMENT_3D('',#1800,#1801,#1802);
#1804=PLANE('',#1803);
#1805=ORIENTED_EDGE('',*,*,#926,.T.);
#1806=ORIENTED_EDGE('',*,*,#596,.F.);
#1807=ORIENTED_EDGE('',*,*,#1765,.F.);
#1808=ORIENTED_EDGE('',*,*,#569,.F.);
#1809=EDGE_LOOP('',(#1805,#1806,#1807,#1808));
#1810=FACE_BOUND('',#1809,.T.);
#1811=ADVANCED_FACE('F1376',(#1810),#1804,.F.);
#1812=CARTESIAN_POINT('',(-14.1715728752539,20.9,11.));
#1813=DIRECTION('',(0.,0.,-1.));
#1814=DIRECTION('',(-1.,0.,0.));
#1815=AXIS2_PLACEMENT_3D('',#1812,#1813,#1814);
#1816=PLANE('',#1815);
#1817=ORIENTED_EDGE('',*,*,#533,.T.);
#1818=DIRECTION('',(0.,1.,0.));
#1819=VECTOR('',#1818,1.);
#1820=CARTESIAN_POINT('',(-14.1715728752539,20.9,11.));
#1821=LINE('',#1820,#1819);
#1822=CARTESIAN_POINT('',(-14.1715728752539,20.9,11.));
#1823=VERTEX_POINT('',#1822);
#1824=EDGE_CURVE('E492',#1823,#532,#1821,.T.);
#1825=ORIENTED_EDGE('',*,*,#1824,.F.);
#1826=DIRECTION('',(-1.,0.,0.));
#1827=VECTOR('',#1826,1.);
#1828=CARTESIAN_POINT('',(-14.1715728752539,20.9,11.));
#1829=LINE('',#1828,#1827);
#1830=CARTESIAN_POINT('',(14.1715728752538,20.9,11.));
#1831=VERTEX_POINT('',#1830);
#1832=EDGE_CURVE('E478',#1831,#1823,#1829,.T.);
#1833=ORIENTED_EDGE('',*,*,#1832,.F.);
#1834=DIRECTION('',(0.,1.,0.));
#1835=VECTOR('',#1834,1.);
#1836=CARTESIAN_POINT('',(14.1715728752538,20.9,11.));
#1837=LINE('',#1836,#1835);
#1838=EDGE_CURVE('E495',#1831,#530,#1837,.T.);
#1839=ORIENTED_EDGE('',*,*,#1838,.T.);
#1840=EDGE_LOOP('',(#1817,#1825,#1833,#1839));
#1841=FACE_BOUND('',#1840,.T.);
#1842=ADVANCED_FACE('F1366',(#1841),#1816,.F.);
#1843=CARTESIAN_POINT('',(14.1715728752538,20.9,12.5));
#1844=DIRECTION('',(1.,0.,0.));
#1845=DIRECTION('',(0.,0.,-1.));
#1846=AXIS2_PLACEMENT_3D('',#1843,#1844,#1845);
#1847=PLANE('',#1846);
#1848=ORIENTED_EDGE('',*,*,#284,.T.);
#1849=ORIENTED_EDGE('',*,*,#1715,.T.);
#1850=ORIENTED_EDGE('',*,*,#537,.T.);
#1851=ORIENTED_EDGE('',*,*,#1838,.F.);
#1852=DIRECTION('',(0.,0.,-1.));
#1853=VECTOR('',#1852,1.);
#1854=CARTESIAN_POINT('',(14.1715728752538,20.9,26.5));
#1855=LINE('',#1854,#1853);
#1856=CARTESIAN_POINT('',(14.1715728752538,20.9,28.));
#1857=VERTEX_POINT('',#1856);
#1858=EDGE_CURVE('E476',#1857,#1831,#1855,.T.);
#1859=ORIENTED_EDGE('',*,*,#1858,.F.);
#1860=DIRECTION('',(0.,1.,0.));
#1861=VECTOR('',#1860,1.);
#1862=CARTESIAN_POINT('',(14.1715728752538,20.9,28.));
#1863=LINE('',#1862,#1861);
#1864=EDGE_CURVE('E498',#1857,#283,#1863,.T.);
#1865=ORIENTED_EDGE('',*,*,#1864,.T.);
#1866=EDGE_LOOP('',(#1848,#1849,#1850,#1851,#1859,#1865));
#1867=FACE_BOUND('',#1866,.T.);
#1868=ADVANCED_FACE('F1356',(#1867),#1847,.F.);
#1869=CARTESIAN_POINT('',(-14.1715728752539,20.9,28.));
#1870=DIRECTION('',(0.,0.,1.));
#1871=DIRECTION('',(1.,0.,0.));
#1872=AXIS2_PLACEMENT_3D('',#1869,#1870,#1871);
#1873=PLANE('',#1872);
#1874=ORIENTED_EDGE('',*,*,#292,.T.);
#1875=ORIENTED_EDGE('',*,*,#1864,.F.);
#1876=DIRECTION('',(1.,0.,0.));
#1877=VECTOR('',#1876,1.);
#1878=CARTESIAN_POINT('',(-14.1715728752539,20.9,28.));
#1879=LINE('',#1878,#1877);
#1880=CARTESIAN_POINT('',(-14.1715728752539,20.9,28.));
#1881=VERTEX_POINT('',#1880);
#1882=EDGE_CURVE('E472',#1881,#1857,#1879,.T.);
#1883=ORIENTED_EDGE('',*,*,#1882,.F.);
#1884=DIRECTION('',(0.,1.,0.));
#1885=VECTOR('',#1884,1.);
#1886=CARTESIAN_POINT('',(-14.1715728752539,20.9,28.));
#1887=LINE('',#1886,#1885);
#1888=EDGE_CURVE('E481',#1881,#291,#1887,.T.);
#1889=ORIENTED_EDGE('',*,*,#1888,.T.);
#1890=EDGE_LOOP('',(#1874,#1875,#1883,#1889));
#1891=FACE_BOUND('',#1890,.T.);
#1892=ADVANCED_FACE('F1345',(#1891),#1873,.F.);
#1893=CARTESIAN_POINT('',(-14.1715728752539,20.9,26.5));
#1894=DIRECTION('',(-1.,0.,0.));
#1895=DIRECTION('',(0.,0.,1.));
#1896=AXIS2_PLACEMENT_3D('',#1893,#1894,#1895);
#1897=PLANE('',#1896);
#1898=ORIENTED_EDGE('',*,*,#571,.T.);
#1899=ORIENTED_EDGE('',*,*,#1783,.T.);
#1900=ORIENTED_EDGE('',*,*,#300,.T.);
#1901=ORIENTED_EDGE('',*,*,#1888,.F.);
#1902=DIRECTION('',(0.,0.,1.));
#1903=VECTOR('',#1902,1.);
#1904=CARTESIAN_POINT('',(-14.1715728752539,20.9,12.5));
#1905=LINE('',#1904,#1903);
#1906=EDGE_CURVE('E470',#1823,#1881,#1905,.T.);
#1907=ORIENTED_EDGE('',*,*,#1906,.F.);
#1908=ORIENTED_EDGE('',*,*,#1824,.T.);
#1909=EDGE_LOOP('',(#1898,#1899,#1900,#1901,#1907,#1908));
#1910=FACE_BOUND('',#1909,.T.);
#1911=ADVANCED_FACE('F1333',(#1910),#1897,.F.);
#1912=CARTESIAN_POINT('',(0.,20.9,0.));
#1913=DIRECTION('',(0.,-1.,0.));
#1914=DIRECTION('',(0.,0.,-1.));
#1915=AXIS2_PLACEMENT_3D('',#1912,#1913,#1914);
#1916=PLANE('',#1915);
#1917=ORIENTED_EDGE('',*,*,#1906,.T.);
#1918=ORIENTED_EDGE('',*,*,#1882,.T.);
#1919=ORIENTED_EDGE('',*,*,#1858,.T.);
#1920=ORIENTED_EDGE('',*,*,#1832,.T.);
#1921=EDGE_LOOP('',(#1917,#1918,#1919,#1920));
#1922=FACE_BOUND('',#1921,.T.);
#1923=ADVANCED_FACE('F1328',(#1922),#1916,.F.);
#1924=CARTESIAN_POINT('',(-20.9,-14.1715728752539,11.));
#1925=DIRECTION('',(0.,0.,-1.));
#1926=DIRECTION('',(-1.,0.,0.));
#1927=AXIS2_PLACEMENT_3D('',#1924,#1925,#1926);
#1928=PLANE('',#1927);
#1929=ORIENTED_EDGE('',*,*,#584,.T.);
#1930=DIRECTION('',(-1.,0.,0.));
#1931=VECTOR('',#1930,1.);
#1932=CARTESIAN_POINT('',(-20.9,-14.1715728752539,11.));
#1933=LINE('',#1932,#1931);
#1934=CARTESIAN_POINT('',(-20.9,-14.1715728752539,11.));
#1935=VERTEX_POINT('',#1934);
#1936=EDGE_CURVE('E460',#1935,#583,#1933,.T.);
#1937=ORIENTED_EDGE('',*,*,#1936,.F.);
#1938=DIRECTION('',(0.,-1.,0.));
#1939=VECTOR('',#1938,1.);
#1940=CARTESIAN_POINT('',(-20.9,-14.1715728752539,11.));
#1941=LINE('',#1940,#1939);
#1942=CARTESIAN_POINT('',(-20.9000000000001,14.1715728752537,11.));
#1943=VERTEX_POINT('',#1942);
#1944=EDGE_CURVE('E446',#1943,#1935,#1941,.T.);
#1945=ORIENTED_EDGE('',*,*,#1944,.F.);
#1946=DIRECTION('',(-1.,0.,0.));
#1947=VECTOR('',#1946,1.);
#1948=CARTESIAN_POINT('',(-20.9000000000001,14.1715728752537,11.));
#1949=LINE('',#1948,#1947);
#1950=EDGE_CURVE('E463',#1943,#581,#1949,.T.);
#1951=ORIENTED_EDGE('',*,*,#1950,.T.);
#1952=EDGE_LOOP('',(#1929,#1937,#1945,#1951));
#1953=FACE_BOUND('',#1952,.T.);
#1954=ADVANCED_FACE('F1332',(#1953),#1928,.F.);
#1955=CARTESIAN_POINT('',(-20.9000000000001,14.1715728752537,12.5));
#1956=DIRECTION('',(0.,1.,0.));
#1957=DIRECTION('',(-1.,0.,0.));
#1958=AXIS2_PLACEMENT_3D('',#1955,#1956,#1957);
#1959=PLANE('',#1958);
#1960=ORIENTED_EDGE('',*,*,#212,.T.);
#1961=ORIENTED_EDGE('',*,*,#1771,.T.);
#1962=ORIENTED_EDGE('',*,*,#588,.T.);
#1963=ORIENTED_EDGE('',*,*,#1950,.F.);
#1964=DIRECTION('',(0.,0.,-1.));
#1965=VECTOR('',#1964,1.);
#1966=CARTESIAN_POINT('',(-20.9000000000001,14.1715728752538,26.5));
#1967=LINE('',#1966,#1965);
#1968=CARTESIAN_POINT('',(-20.9000000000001,14.1715728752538,28.));
#1969=VERTEX_POINT('',#1968);
#1970=EDGE_CURVE('E444',#1969,#1943,#1967,.T.);
#1971=ORIENTED_EDGE('',*,*,#1970,.F.);
#1972=DIRECTION('',(-1.,0.,0.));
#1973=VECTOR('',#1972,1.);
#1974=CARTESIAN_POINT('',(-20.9000000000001,14.1715728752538,28.));
#1975=LINE('',#1974,#1973);
#1976=EDGE_CURVE('E466',#1969,#211,#1975,.T.);
#1977=ORIENTED_EDGE('',*,*,#1976,.T.);
#1978=EDGE_LOOP('',(#1960,#1961,#1962,#1963,#1971,#1977));
#1979=FACE_BOUND('',#1978,.T.);
#1980=ADVANCED_FACE('F1627',(#1979),#1959,.F.);
#1981=CARTESIAN_POINT('',(-20.9,-14.1715728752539,28.));
#1982=DIRECTION('',(0.,0.,1.));
#1983=DIRECTION('',(1.,0.,0.));
#1984=AXIS2_PLACEMENT_3D('',#1981,#1982,#1983);
#1985=PLANE('',#1984);
#1986=ORIENTED_EDGE('',*,*,#220,.T.);
#1987=ORIENTED_EDGE('',*,*,#1976,.F.);
#1988=DIRECTION('',(0.,1.,0.));
#1989=VECTOR('',#1988,1.);
#1990=CARTESIAN_POINT('',(-20.9,-14.1715728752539,28.));
#1991=LINE('',#1990,#1989);
#1992=CARTESIAN_POINT('',(-20.9,-14.1715728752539,28.));
#1993=VERTEX_POINT('',#1992);
#1994=EDGE_CURVE('E440',#1993,#1969,#1991,.T.);
#1995=ORIENTED_EDGE('',*,*,#1994,.F.);
#1996=DIRECTION('',(-1.,0.,0.));
#1997=VECTOR('',#1996,1.);
#1998=CARTESIAN_POINT('',(-20.9,-14.1715728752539,28.));
#1999=LINE('',#1998,#1997);
#2000=EDGE_CURVE('E449',#1993,#219,#1999,.T.);
#2001=ORIENTED_EDGE('',*,*,#2000,.T.);
#2002=EDGE_LOOP('',(#1986,#1987,#1995,#2001));
#2003=FACE_BOUND('',#2002,.T.);
#2004=ADVANCED_FACE('F1623',(#2003),#1985,.F.);
#2005=CARTESIAN_POINT('',(-20.9,-14.1715728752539,26.5));
#2006=DIRECTION('',(0.,-1.,0.));
#2007=DIRECTION('',(1.,0.,0.));
#2008=AXIS2_PLACEMENT_3D('',#2005,#2006,#2007);
#2009=PLANE('',#2008);
#2010=ORIENTED_EDGE('',*,*,#622,.T.);
#2011=ORIENTED_EDGE('',*,*,#1615,.T.);
#2012=ORIENTED_EDGE('',*,*,#228,.T.);
#2013=ORIENTED_EDGE('',*,*,#2000,.F.);
#2014=DIRECTION('',(0.,0.,1.));
#2015=VECTOR('',#2014,1.);
#2016=CARTESIAN_POINT('',(-20.9,-14.1715728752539,12.5));
#2017=LINE('',#2016,#2015);
#2018=EDGE_CURVE('E438',#1935,#1993,#2017,.T.);
#2019=ORIENTED_EDGE('',*,*,#2018,.F.);
#2020=ORIENTED_EDGE('',*,*,#1936,.T.);
#2021=EDGE_LOOP('',(#2010,#2011,#2012,#2013,#2019,#2020));
#2022=FACE_BOUND('',#2021,.T.);
#2023=ADVANCED_FACE('F1619',(#2022),#2009,.F.);
#2024=CARTESIAN_POINT('',(-20.9,0.,0.));
#2025=DIRECTION('',(1.,0.,0.));
#2026=DIRECTION('',(0.,0.,-1.));
#2027=AXIS2_PLACEMENT_3D('',#2024,#2025,#2026);
#2028=PLANE('',#2027);
#2029=ORIENTED_EDGE('',*,*,#2018,.T.);
#2030=ORIENTED_EDGE('',*,*,#1994,.T.);
#2031=ORIENTED_EDGE('',*,*,#1970,.T.);
#2032=ORIENTED_EDGE('',*,*,#1944,.T.);
#2033=EDGE_LOOP('',(#2029,#2030,#2031,#2032));
#2034=FACE_BOUND('',#2033,.T.);
#2035=ADVANCED_FACE('F1622',(#2034),#2028,.F.);
#2036=CARTESIAN_POINT('',(14.1715728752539,-20.9,11.));
#2037=DIRECTION('',(0.,0.,-1.));
#2038=DIRECTION('',(-1.,0.,0.));
#2039=AXIS2_PLACEMENT_3D('',#2036,#2037,#2038);
#2040=PLANE('',#2039);
#2041=ORIENTED_EDGE('',*,*,#635,.T.);
#2042=DIRECTION('',(0.,-1.,0.));
#2043=VECTOR('',#2042,1.);
#2044=CARTESIAN_POINT('',(14.1715728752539,-20.9,11.));
#2045=LINE('',#2044,#2043);
#2046=CARTESIAN_POINT('',(14.1715728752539,-20.9,11.));
#2047=VERTEX_POINT('',#2046);
#2048=EDGE_CURVE('E428',#2047,#634,#2045,.T.);
#2049=ORIENTED_EDGE('',*,*,#2048,.F.);
#2050=DIRECTION('',(1.,0.,0.));
#2051=VECTOR('',#2050,1.);
#2052=CARTESIAN_POINT('',(14.1715728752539,-20.9,11.));
#2053=LINE('',#2052,#2051);
#2054=CARTESIAN_POINT('',(-14.1715728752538,-20.9,11.));
#2055=VERTEX_POINT('',#2054);
#2056=EDGE_CURVE('E414',#2055,#2047,#2053,.T.);
#2057=ORIENTED_EDGE('',*,*,#2056,.F.);
#2058=DIRECTION('',(0.,-1.,0.));
#2059=VECTOR('',#2058,1.);
#2060=CARTESIAN_POINT('',(-14.1715728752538,-20.9,11.));
#2061=LINE('',#2060,#2059);
#2062=EDGE_CURVE('E431',#2055,#632,#2061,.T.);
#2063=ORIENTED_EDGE('',*,*,#2062,.T.);
#2064=EDGE_LOOP('',(#2041,#2049,#2057,#2063));
#2065=FACE_BOUND('',#2064,.T.);
#2066=ADVANCED_FACE('F1635',(#2065),#2040,.F.);
#2067=CARTESIAN_POINT('',(-14.1715728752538,-20.9,12.5));
#2068=DIRECTION('',(-1.,0.,0.));
#2069=DIRECTION('',(0.,0.,1.));
#2070=AXIS2_PLACEMENT_3D('',#2067,#2068,#2069);
#2071=PLANE('',#2070);
#2072=ORIENTED_EDGE('',*,*,#140,.T.);
#2073=ORIENTED_EDGE('',*,*,#1603,.T.);
#2074=ORIENTED_EDGE('',*,*,#639,.T.);
#2075=ORIENTED_EDGE('',*,*,#2062,.F.);
#2076=DIRECTION('',(0.,0.,-1.));
#2077=VECTOR('',#2076,1.);
#2078=CARTESIAN_POINT('',(-14.1715728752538,-20.9,26.5));
#2079=LINE('',#2078,#2077);
#2080=CARTESIAN_POINT('',(-14.1715728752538,-20.9,28.));
#2081=VERTEX_POINT('',#2080);
#2082=EDGE_CURVE('E412',#2081,#2055,#2079,.T.);
#2083=ORIENTED_EDGE('',*,*,#2082,.F.);
#2084=DIRECTION('',(0.,-1.,0.));
#2085=VECTOR('',#2084,1.);
#2086=CARTESIAN_POINT('',(-14.1715728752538,-20.9,28.));
#2087=LINE('',#2086,#2085);
#2088=EDGE_CURVE('E434',#2081,#139,#2087,.T.);
#2089=ORIENTED_EDGE('',*,*,#2088,.T.);
#2090=EDGE_LOOP('',(#2072,#2073,#2074,#2075,#2083,#2089));
#2091=FACE_BOUND('',#2090,.T.);
#2092=ADVANCED_FACE('F1645',(#2091),#2071,.F.);
#2093=CARTESIAN_POINT('',(14.1715728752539,-20.9,28.));
#2094=DIRECTION('',(0.,0.,1.));
#2095=DIRECTION('',(1.,0.,0.));
#2096=AXIS2_PLACEMENT_3D('',#2093,#2094,#2095);
#2097=PLANE('',#2096);
#2098=ORIENTED_EDGE('',*,*,#148,.T.);
#2099=ORIENTED_EDGE('',*,*,#2088,.F.);
#2100=DIRECTION('',(-1.,0.,0.));
#2101=VECTOR('',#2100,1.);
#2102=CARTESIAN_POINT('',(14.1715728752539,-20.9,28.));
#2103=LINE('',#2102,#2101);
#2104=CARTESIAN_POINT('',(14.1715728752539,-20.9,28.));
#2105=VERTEX_POINT('',#2104);
#2106=EDGE_CURVE('E408',#2105,#2081,#2103,.T.);
#2107=ORIENTED_EDGE('',*,*,#2106,.F.);
#2108=DIRECTION('',(0.,-1.,0.));
#2109=VECTOR('',#2108,1.);
#2110=CARTESIAN_POINT('',(14.1715728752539,-20.9,28.));
#2111=LINE('',#2110,#2109);
#2112=EDGE_CURVE('E417',#2105,#147,#2111,.T.);
#2113=ORIENTED_EDGE('',*,*,#2112,.T.);
#2114=EDGE_LOOP('',(#2098,#2099,#2107,#2113));
#2115=FACE_BOUND('',#2114,.T.);
#2116=ADVANCED_FACE('F1641',(#2115),#2097,.F.);
#2117=CARTESIAN_POINT('',(14.1715728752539,-20.9,26.5));
#2118=DIRECTION('',(1.,0.,0.));
#2119=DIRECTION('',(0.,0.,-1.));
#2120=AXIS2_PLACEMENT_3D('',#2117,#2118,#2119);
#2121=PLANE('',#2120);
#2122=ORIENTED_EDGE('',*,*,#673,.T.);
#2123=ORIENTED_EDGE('',*,*,#1659,.T.);
#2124=ORIENTED_EDGE('',*,*,#156,.T.);
#2125=ORIENTED_EDGE('',*,*,#2112,.F.);
#2126=DIRECTION('',(0.,0.,1.));
#2127=VECTOR('',#2126,1.);
#2128=CARTESIAN_POINT('',(14.1715728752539,-20.9,12.5));
#2129=LINE('',#2128,#2127);
#2130=EDGE_CURVE('E406',#2047,#2105,#2129,.T.);
#2131=ORIENTED_EDGE('',*,*,#2130,.F.);
#2132=ORIENTED_EDGE('',*,*,#2048,.T.);
#2133=EDGE_LOOP('',(#2122,#2123,#2124,#2125,#2131,#2132));
#2134=FACE_BOUND('',#2133,.T.);
#2135=ADVANCED_FACE('F1637',(#2134),#2121,.F.);
#2136=CARTESIAN_POINT('',(0.,-20.9,0.));
#2137=DIRECTION('',(0.,1.,0.));
#2138=DIRECTION('',(0.,0.,-1.));
#2139=AXIS2_PLACEMENT_3D('',#2136,#2137,#2138);
#2140=PLANE('',#2139);
#2141=ORIENTED_EDGE('',*,*,#2130,.T.);
#2142=ORIENTED_EDGE('',*,*,#2106,.T.);
#2143=ORIENTED_EDGE('',*,*,#2082,.T.);
#2144=ORIENTED_EDGE('',*,*,#2056,.T.);
#2145=EDGE_LOOP('',(#2141,#2142,#2143,#2144));
#2146=FACE_BOUND('',#2145,.T.);
#2147=ADVANCED_FACE('F1640',(#2146),#2140,.F.);
#2148=CARTESIAN_POINT('',(20.8999999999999,14.1715728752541,11.));
#2149=DIRECTION('',(0.,0.,-1.));
#2150=DIRECTION('',(-1.,0.,0.));
#2151=AXIS2_PLACEMENT_3D('',#2148,#2149,#2150);
#2152=PLANE('',#2151);
#2153=ORIENTED_EDGE('',*,*,#482,.T.);
#2154=DIRECTION('',(1.,0.,0.));
#2155=VECTOR('',#2154,1.);
#2156=CARTESIAN_POINT('',(20.8999999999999,14.1715728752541,11.));
#2157=LINE('',#2156,#2155);
#2158=CARTESIAN_POINT('',(20.8999999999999,14.1715728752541,11.));
#2159=VERTEX_POINT('',#2158);
#2160=EDGE_CURVE('E399',#2159,#481,#2157,.T.);
#2161=ORIENTED_EDGE('',*,*,#2160,.F.);
#2162=DIRECTION('',(0.,1.,0.));
#2163=VECTOR('',#2162,1.);
#2164=CARTESIAN_POINT('',(20.8999999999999,14.1715728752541,11.));
#2165=LINE('',#2164,#2163);
#2166=CARTESIAN_POINT('',(20.9000000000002,-14.1715728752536,11.));
#2167=VERTEX_POINT('',#2166);
#2168=EDGE_CURVE('E368',#2167,#2159,#2165,.T.);
#2169=ORIENTED_EDGE('',*,*,#2168,.F.);
#2170=DIRECTION('',(1.,0.,0.));
#2171=VECTOR('',#2170,1.);
#2172=CARTESIAN_POINT('',(20.9000000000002,-14.1715728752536,11.));
#2173=LINE('',#2172,#2171);
#2174=EDGE_CURVE('E402',#2167,#479,#2173,.T.);
#2175=ORIENTED_EDGE('',*,*,#2174,.T.);
#2176=EDGE_LOOP('',(#2153,#2161,#2169,#2175));
#2177=FACE_BOUND('',#2176,.T.);
#2178=ADVANCED_FACE('F1655',(#2177),#2152,.F.);
#2179=CARTESIAN_POINT('',(20.9000000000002,-14.1715728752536,12.5));
#2180=DIRECTION('',(0.,-1.,0.));
#2181=DIRECTION('',(1.,0.,0.));
#2182=AXIS2_PLACEMENT_3D('',#2179,#2180,#2181);
#2183=PLANE('',#2182);
#2184=ORIENTED_EDGE('',*,*,#68,.T.);
#2185=ORIENTED_EDGE('',*,*,#1671,.T.);
#2186=ORIENTED_EDGE('',*,*,#486,.T.);
#2187=ORIENTED_EDGE('',*,*,#2174,.F.);
#2188=DIRECTION('',(0.,0.,-1.));
#2189=VECTOR('',#2188,1.);
#2190=CARTESIAN_POINT('',(20.9000000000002,-14.1715728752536,26.5));
#2191=LINE('',#2190,#2189);
#2192=CARTESIAN_POINT('',(20.9000000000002,-14.1715728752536,28.));
#2193=VERTEX_POINT('',#2192);
#2194=EDGE_CURVE('E384',#2193,#2167,#2191,.T.);
#2195=ORIENTED_EDGE('',*,*,#2194,.F.);
#2196=DIRECTION('',(1.,0.,0.));
#2197=VECTOR('',#2196,1.);
#2198=CARTESIAN_POINT('',(20.9000000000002,-14.1715728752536,28.));
#2199=LINE('',#2198,#2197);
#2200=EDGE_CURVE('E380',#2193,#67,#2199,.T.);
#2201=ORIENTED_EDGE('',*,*,#2200,.T.);
#2202=EDGE_LOOP('',(#2184,#2185,#2186,#2187,#2195,#2201));
#2203=FACE_BOUND('',#2202,.T.);
#2204=ADVANCED_FACE('F1661',(#2203),#2183,.F.);
#2205=CARTESIAN_POINT('',(20.8999999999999,14.1715728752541,28.));
#2206=DIRECTION('',(0.,0.,1.));
#2207=DIRECTION('',(1.,0.,0.));
#2208=AXIS2_PLACEMENT_3D('',#2205,#2206,#2207);
#2209=PLANE('',#2208);
#2210=ORIENTED_EDGE('',*,*,#76,.T.);
#2211=ORIENTED_EDGE('',*,*,#2200,.F.);
#2212=DIRECTION('',(0.,-1.,0.));
#2213=VECTOR('',#2212,1.);
#2214=CARTESIAN_POINT('',(20.8999999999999,14.1715728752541,28.));
#2215=LINE('',#2214,#2213);
#2216=CARTESIAN_POINT('',(20.8999999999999,14.1715728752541,28.));
#2217=VERTEX_POINT('',#2216);
#2218=EDGE_CURVE('E366',#2217,#2193,#2215,.T.);
#2219=ORIENTED_EDGE('',*,*,#2218,.F.);
#2220=DIRECTION('',(1.,0.,0.));
#2221=VECTOR('',#2220,1.);
#2222=CARTESIAN_POINT('',(20.8999999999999,14.1715728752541,28.));
#2223=LINE('',#2222,#2221);
#2224=EDGE_CURVE('E373',#2217,#75,#2223,.T.);
#2225=ORIENTED_EDGE('',*,*,#2224,.T.);
#2226=EDGE_LOOP('',(#2210,#2211,#2219,#2225));
#2227=FACE_BOUND('',#2226,.T.);
#2228=ADVANCED_FACE('F382',(#2227),#2209,.F.);
#2229=CARTESIAN_POINT('',(20.8999999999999,14.1715728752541,26.5));
#2230=DIRECTION('',(0.,1.,0.));
#2231=DIRECTION('',(-1.,0.,0.));
#2232=AXIS2_PLACEMENT_3D('',#2229,#2230,#2231);
#2233=PLANE('',#2232);
#2234=ORIENTED_EDGE('',*,*,#520,.T.);
#2235=ORIENTED_EDGE('',*,*,#1727,.T.);
#2236=ORIENTED_EDGE('',*,*,#84,.T.);
#2237=ORIENTED_EDGE('',*,*,#2224,.F.);
#2238=DIRECTION('',(0.,0.,1.));
#2239=VECTOR('',#2238,1.);
#2240=CARTESIAN_POINT('',(20.8999999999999,14.1715728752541,12.5));
#2241=LINE('',#2240,#2239);
#2242=EDGE_CURVE('E362',#2159,#2217,#2241,.T.);
#2243=ORIENTED_EDGE('',*,*,#2242,.F.);
#2244=ORIENTED_EDGE('',*,*,#2160,.T.);
#2245=EDGE_LOOP('',(#2234,#2235,#2236,#2237,#2243,#2244));
#2246=FACE_BOUND('',#2245,.T.);
#2247=ADVANCED_FACE('F374',(#2246),#2233,.F.);
#2248=CARTESIAN_POINT('',(20.9,2.18915879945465E-13,0.));
#2249=DIRECTION('',(-1.,0.,0.));
#2250=DIRECTION('',(0.,0.,-1.));
#2251=AXIS2_PLACEMENT_3D('',#2248,#2249,#2250);
#2252=PLANE('',#2251);
#2253=ORIENTED_EDGE('',*,*,#2242,.T.);
#2254=ORIENTED_EDGE('',*,*,#2218,.T.);
#2255=ORIENTED_EDGE('',*,*,#2194,.T.);
#2256=ORIENTED_EDGE('',*,*,#2168,.T.);
#2257=EDGE_LOOP('',(#2253,#2254,#2255,#2256));
#2258=FACE_BOUND('',#2257,.T.);
#2259=ADVANCED_FACE('F364',(#2258),#2252,.F.);
#2260=CARTESIAN_POINT('',(0.,0.,36.));
#2261=DIRECTION('',(0.,0.,1.));
#2262=DIRECTION('',(1.,0.,0.));
#2263=AXIS2_PLACEMENT_3D('',#2260,#2261,#2262);
#2264=CYLINDRICAL_SURFACE('',#2263,5.);
#2265=ORIENTED_EDGE('',*,*,#31,.F.);
#2266=EDGE_LOOP('',(#2265));
#2267=FACE_BOUND('',#2266,.T.);
#2268=ORIENTED_EDGE('',*,*,#690,.T.);
#2269=EDGE_LOOP('',(#2268));
#2270=FACE_BOUND('',#2269,.T.);
#2271=ADVANCED_FACE('F983',(#2267,#2270),#2264,.F.);
#2272=CARTESIAN_POINT('',(0.,0.,36.1));
#2273=DIRECTION('',(0.,0.,1.));
#2274=DIRECTION('',(1.,0.,0.));
#2275=AXIS2_PLACEMENT_3D('',#2272,#2273,#2274);
#2276=PLANE('',#2275);
#2277=CARTESIAN_POINT('',(0.,0.,36.1));
#2278=DIRECTION('',(0.,0.,1.));
#2279=DIRECTION('',(1.,0.,0.));
#2280=AXIS2_PLACEMENT_3D('',#2277,#2278,#2279);
#2281=CIRCLE('',#2280,4.65);
#2282=CARTESIAN_POINT('',(4.65,0.,36.1));
#2283=VERTEX_POINT('',#2282);
#2284=EDGE_CURVE('E992',#2283,#2283,#2281,.T.);
#2285=ORIENTED_EDGE('',*,*,#2284,.T.);
#2286=EDGE_LOOP('',(#2285));
#2287=FACE_BOUND('',#2286,.T.);
#2288=CARTESIAN_POINT('',(0.,0.,36.1));
#2289=DIRECTION('',(0.,0.,1.));
#2290=DIRECTION('',(1.,0.,0.));
#2291=AXIS2_PLACEMENT_3D('',#2288,#2289,#2290);
#2292=CIRCLE('',#2291,2.5);
#2293=CARTESIAN_POINT('',(2.5,0.,36.1));
#2294=VERTEX_POINT('',#2293);
#2295=EDGE_CURVE('E994',#2294,#2294,#2292,.T.);
#2296=ORIENTED_EDGE('',*,*,#2295,.F.);
#2297=EDGE_LOOP('',(#2296));
#2298=FACE_BOUND('',#2297,.T.);
#2299=ADVANCED_FACE('F978',(#2287,#2298),#2276,.T.);
#2300=CARTESIAN_POINT('',(0.,0.,36.1));
#2301=DIRECTION('',(0.,0.,-1.));
#2302=DIRECTION('',(-1.,0.,0.));
#2303=AXIS2_PLACEMENT_3D('',#2300,#2301,#2302);
#2304=CYLINDRICAL_SURFACE('',#2303,4.65);
#2305=ORIENTED_EDGE('',*,*,#2284,.F.);
#2306=EDGE_LOOP('',(#2305));
#2307=FACE_BOUND('',#2306,.T.);
#2308=ORIENTED_EDGE('',*,*,#42,.T.);
#2309=EDGE_LOOP('',(#2308));
#2310=FACE_BOUND('',#2309,.T.);
#2311=ADVANCED_FACE('F970',(#2307,#2310),#2304,.T.);
#2312=CARTESIAN_POINT('',(0.,0.,36.1));
#2313=DIRECTION('',(0.,0.,-1.));
#2314=DIRECTION('',(-1.,0.,0.));
#2315=AXIS2_PLACEMENT_3D('',#2312,#2313,#2314);
#2316=CYLINDRICAL_SURFACE('',#2315,2.5);
#2317=ORIENTED_EDGE('',*,*,#2295,.T.);
#2318=EDGE_LOOP('',(#2317));
#2319=FACE_BOUND('',#2318,.T.);
#2320=CARTESIAN_POINT('',(0.,0.,36.));
#2321=DIRECTION('',(0.,0.,1.));
#2322=DIRECTION('',(1.,0.,0.));
#2323=AXIS2_PLACEMENT_3D('',#2320,#2321,#2322);
#2324=CIRCLE('',#2323,2.5);
#2325=CARTESIAN_POINT('',(2.5,0.,36.));
#2326=VERTEX_POINT('',#2325);
#2327=EDGE_CURVE('E11',#2326,#2326,#2324,.F.);
#2328=ORIENTED_EDGE('',*,*,#2327,.T.);
#2329=EDGE_LOOP('',(#2328));
#2330=FACE_BOUND('',#2329,.T.);
#2331=ADVANCED_FACE('F965',(#2319,#2330),#2316,.F.);
#2332=ORIENTED_EDGE('',*,*,#2327,.F.);
#2333=EDGE_LOOP('',(#2332));
#2334=FACE_BOUND('',#2333,.T.);
#2335=ADVANCED_FACE('F955',(#2334),#23,.T.);
#2336=CLOSED_SHELL('',(#46,#118,#190,#262,#334,#356,#378,#400,#422,#450,#473,#524,#575,#626,
#677,#760,#887,#904,#921,#938,#955,#977,#994,#1011,#1028,#1045,#1062,#1079,#1091,#1113,#1130,
#1147,#1164,#1181,#1198,#1215,#1227,#1239,#1267,#1279,#1291,#1336,#1361,#1442,#1457,#1471,#1491,
#1500,#1520,#1529,#1549,#1558,#1578,#1587,#1619,#1631,#1643,#1675,#1687,#1699,#1731,#1743,#1755,
#1787,#1799,#1811,#1842,#1868,#1892,#1911,#1923,#1954,#1980,#2004,#2023,#2035,#2066,#2092,#2116,
#2135,#2147,#2178,#2204,#2228,#2247,#2259,#2271,#2299,#2311,#2331,#2335));
#2337=MANIFOLD_SOLID_BREP('B2',#2336);
#2338=ADVANCED_BREP_SHAPE_REPRESENTATION('',(#18,#2337),#14);
#2339=SHAPE_DEFINITION_REPRESENTATION(#9,#2338);
ENDSEC;
END-ISO-10303-21;
